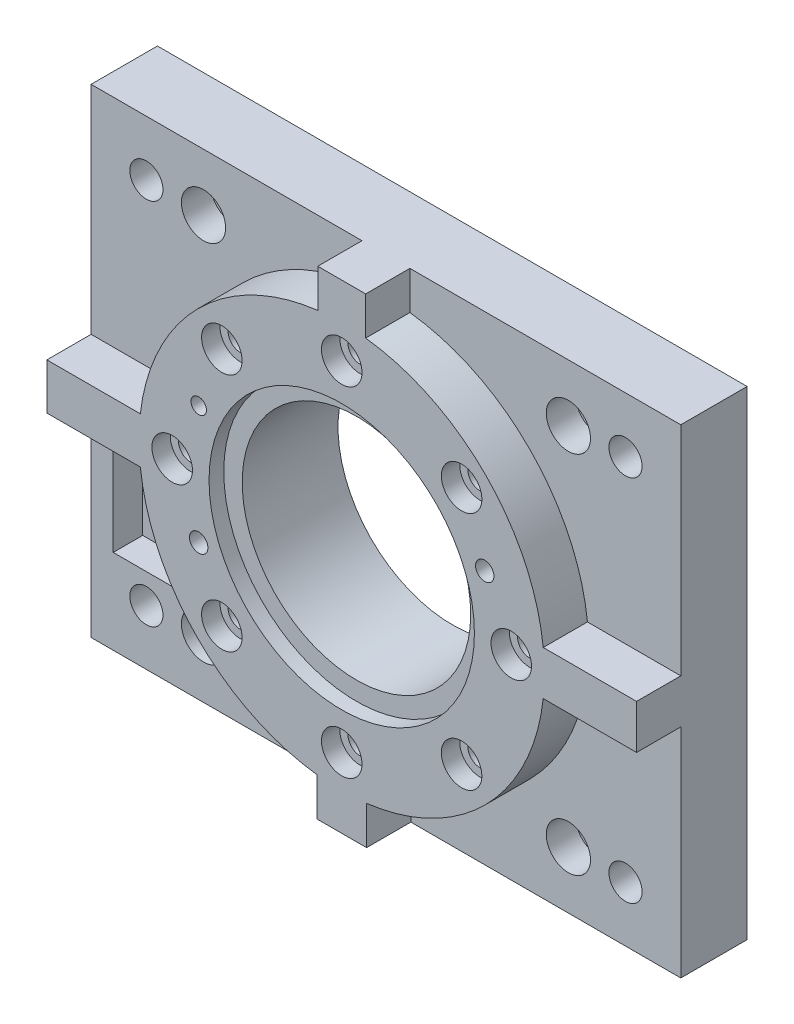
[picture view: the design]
ISO-10303-21;
HEADER;
FILE_DESCRIPTION(('STEP AP214'),'2;1');
FILE_NAME('part.step','',(''),(''),'','','');
FILE_SCHEMA(('AUTOMOTIVE_DESIGN { 1 0 10303 214 1 1 1 1 }'));
ENDSEC;
DATA;
#1=APPLICATION_CONTEXT('core data for automotive mechanical design processes');
#2=APPLICATION_PROTOCOL_DEFINITION('international standard','automotive_design',2000,#1);
#3=PRODUCT_CONTEXT('',#1,'mechanical');
#4=PRODUCT('Part','Part','',(#3));
#5=PRODUCT_RELATED_PRODUCT_CATEGORY('part','',(#4));
#6=PRODUCT_DEFINITION_FORMATION('','',#4);
#7=PRODUCT_DEFINITION_CONTEXT('part definition',#1,'design');
#8=PRODUCT_DEFINITION('design','',#6,#7);
#9=PRODUCT_DEFINITION_SHAPE('','',#8);
#10=(LENGTH_UNIT() NAMED_UNIT(*) SI_UNIT(.MILLI.,.METRE.));
#11=(NAMED_UNIT(*) PLANE_ANGLE_UNIT() SI_UNIT($,.RADIAN.));
#12=(NAMED_UNIT(*) SI_UNIT($,.STERADIAN.) SOLID_ANGLE_UNIT());
#13=UNCERTAINTY_MEASURE_WITH_UNIT(LENGTH_MEASURE(1.E-05),#10,'distance_accuracy_value','');
#14=(GEOMETRIC_REPRESENTATION_CONTEXT(3) GLOBAL_UNCERTAINTY_ASSIGNED_CONTEXT((#13)) GLOBAL_UNIT_ASSIGNED_CONTEXT((#10,
#11,#12)) REPRESENTATION_CONTEXT('',''));
#15=CARTESIAN_POINT('',(0.,0.,0.));
#16=DIRECTION('',(0.,0.,1.));
#17=DIRECTION('',(1.,0.,0.));
#18=AXIS2_PLACEMENT_3D('',#15,#16,#17);
#19=CARTESIAN_POINT('',(32.5269119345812,-32.5269119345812,0.));
#20=DIRECTION('',(0.,0.,1.));
#21=DIRECTION('',(1.,0.,0.));
#22=AXIS2_PLACEMENT_3D('',#19,#20,#21);
#23=CYLINDRICAL_SURFACE('',#22,3.3);
#24=CARTESIAN_POINT('',(32.5269119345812,-32.5269119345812,0.));
#25=DIRECTION('',(0.,0.,1.));
#26=DIRECTION('',(1.,0.,0.));
#27=AXIS2_PLACEMENT_3D('',#24,#25,#26);
#28=CIRCLE('',#27,3.3);
#29=CARTESIAN_POINT('',(35.8269119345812,-32.5269119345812,0.));
#30=VERTEX_POINT('',#29);
#31=EDGE_CURVE('E380',#30,#30,#28,.T.);
#32=ORIENTED_EDGE('',*,*,#31,.F.);
#33=EDGE_LOOP('',(#32));
#34=FACE_BOUND('',#33,.T.);
#35=CARTESIAN_POINT('',(32.5269119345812,-32.5269119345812,25.));
#36=DIRECTION('',(0.,0.,1.));
#37=DIRECTION('',(1.,0.,0.));
#38=AXIS2_PLACEMENT_3D('',#35,#36,#37);
#39=CIRCLE('',#38,3.3);
#40=CARTESIAN_POINT('',(35.8269119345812,-32.5269119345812,25.));
#41=VERTEX_POINT('',#40);
#42=EDGE_CURVE('E52',#41,#41,#39,.F.);
#43=ORIENTED_EDGE('',*,*,#42,.F.);
#44=EDGE_LOOP('',(#43));
#45=FACE_BOUND('',#44,.T.);
#46=ADVANCED_FACE('F47',(#34,#45),#23,.F.);
#47=CARTESIAN_POINT('',(0.,-46.,0.));
#48=DIRECTION('',(0.,0.,1.));
#49=DIRECTION('',(1.,0.,0.));
#50=AXIS2_PLACEMENT_3D('',#47,#48,#49);
#51=CYLINDRICAL_SURFACE('',#50,3.3);
#52=CARTESIAN_POINT('',(0.,-46.,0.));
#53=DIRECTION('',(0.,0.,1.));
#54=DIRECTION('',(1.,0.,0.));
#55=AXIS2_PLACEMENT_3D('',#52,#53,#54);
#56=CIRCLE('',#55,3.3);
#57=CARTESIAN_POINT('',(3.29999999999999,-46.,0.));
#58=VERTEX_POINT('',#57);
#59=EDGE_CURVE('E373',#58,#58,#56,.T.);
#60=ORIENTED_EDGE('',*,*,#59,.F.);
#61=EDGE_LOOP('',(#60));
#62=FACE_BOUND('',#61,.T.);
#63=CARTESIAN_POINT('',(0.,-46.,25.));
#64=DIRECTION('',(0.,0.,1.));
#65=DIRECTION('',(1.,0.,0.));
#66=AXIS2_PLACEMENT_3D('',#63,#64,#65);
#67=CIRCLE('',#66,3.3);
#68=CARTESIAN_POINT('',(3.29999999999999,-46.,25.));
#69=VERTEX_POINT('',#68);
#70=EDGE_CURVE('E577',#69,#69,#67,.F.);
#71=ORIENTED_EDGE('',*,*,#70,.F.);
#72=EDGE_LOOP('',(#71));
#73=FACE_BOUND('',#72,.T.);
#74=ADVANCED_FACE('F587',(#62,#73),#51,.F.);
#75=CARTESIAN_POINT('',(-32.5269119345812,-32.5269119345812,0.));
#76=DIRECTION('',(0.,0.,1.));
#77=DIRECTION('',(1.,0.,0.));
#78=AXIS2_PLACEMENT_3D('',#75,#76,#77);
#79=CYLINDRICAL_SURFACE('',#78,3.3);
#80=CARTESIAN_POINT('',(-32.5269119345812,-32.5269119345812,0.));
#81=DIRECTION('',(0.,0.,1.));
#82=DIRECTION('',(1.,0.,0.));
#83=AXIS2_PLACEMENT_3D('',#80,#81,#82);
#84=CIRCLE('',#83,3.3);
#85=CARTESIAN_POINT('',(-29.2269119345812,-32.5269119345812,0.));
#86=VERTEX_POINT('',#85);
#87=EDGE_CURVE('E367',#86,#86,#84,.T.);
#88=ORIENTED_EDGE('',*,*,#87,.F.);
#89=EDGE_LOOP('',(#88));
#90=FACE_BOUND('',#89,.T.);
#91=CARTESIAN_POINT('',(-32.5269119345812,-32.5269119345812,25.));
#92=DIRECTION('',(0.,0.,1.));
#93=DIRECTION('',(1.,0.,0.));
#94=AXIS2_PLACEMENT_3D('',#91,#92,#93);
#95=CIRCLE('',#94,3.3);
#96=CARTESIAN_POINT('',(-29.2269119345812,-32.5269119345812,25.));
#97=VERTEX_POINT('',#96);
#98=EDGE_CURVE('E573',#97,#97,#95,.F.);
#99=ORIENTED_EDGE('',*,*,#98,.F.);
#100=EDGE_LOOP('',(#99));
#101=FACE_BOUND('',#100,.T.);
#102=ADVANCED_FACE('F595',(#90,#101),#79,.F.);
#103=CARTESIAN_POINT('',(-46.,0.,0.));
#104=DIRECTION('',(0.,0.,1.));
#105=DIRECTION('',(1.,0.,0.));
#106=AXIS2_PLACEMENT_3D('',#103,#104,#105);
#107=CYLINDRICAL_SURFACE('',#106,3.3);
#108=CARTESIAN_POINT('',(-46.,0.,0.));
#109=DIRECTION('',(0.,0.,1.));
#110=DIRECTION('',(1.,0.,0.));
#111=AXIS2_PLACEMENT_3D('',#108,#109,#110);
#112=CIRCLE('',#111,3.3);
#113=CARTESIAN_POINT('',(-42.7,0.,0.));
#114=VERTEX_POINT('',#113);
#115=EDGE_CURVE('E362',#114,#114,#112,.T.);
#116=ORIENTED_EDGE('',*,*,#115,.F.);
#117=EDGE_LOOP('',(#116));
#118=FACE_BOUND('',#117,.T.);
#119=CARTESIAN_POINT('',(-46.,0.,25.));
#120=DIRECTION('',(0.,0.,1.));
#121=DIRECTION('',(1.,0.,0.));
#122=AXIS2_PLACEMENT_3D('',#119,#120,#121);
#123=CIRCLE('',#122,3.3);
#124=CARTESIAN_POINT('',(-42.7,0.,25.));
#125=VERTEX_POINT('',#124);
#126=EDGE_CURVE('E571',#125,#125,#123,.F.);
#127=ORIENTED_EDGE('',*,*,#126,.F.);
#128=EDGE_LOOP('',(#127));
#129=FACE_BOUND('',#128,.T.);
#130=ADVANCED_FACE('F799',(#118,#129),#107,.F.);
#131=CARTESIAN_POINT('',(-32.5269119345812,32.5269119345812,0.));
#132=DIRECTION('',(0.,0.,1.));
#133=DIRECTION('',(1.,0.,0.));
#134=AXIS2_PLACEMENT_3D('',#131,#132,#133);
#135=CYLINDRICAL_SURFACE('',#134,3.3);
#136=CARTESIAN_POINT('',(-32.5269119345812,32.5269119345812,0.));
#137=DIRECTION('',(0.,0.,1.));
#138=DIRECTION('',(1.,0.,0.));
#139=AXIS2_PLACEMENT_3D('',#136,#137,#138);
#140=CIRCLE('',#139,3.3);
#141=CARTESIAN_POINT('',(-29.2269119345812,32.5269119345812,0.));
#142=VERTEX_POINT('',#141);
#143=EDGE_CURVE('E363',#142,#142,#140,.T.);
#144=ORIENTED_EDGE('',*,*,#143,.F.);
#145=EDGE_LOOP('',(#144));
#146=FACE_BOUND('',#145,.T.);
#147=CARTESIAN_POINT('',(-32.5269119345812,32.5269119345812,25.));
#148=DIRECTION('',(0.,0.,1.));
#149=DIRECTION('',(1.,0.,0.));
#150=AXIS2_PLACEMENT_3D('',#147,#148,#149);
#151=CIRCLE('',#150,3.3);
#152=CARTESIAN_POINT('',(-29.2269119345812,32.5269119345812,25.));
#153=VERTEX_POINT('',#152);
#154=EDGE_CURVE('E568',#153,#153,#151,.F.);
#155=ORIENTED_EDGE('',*,*,#154,.F.);
#156=EDGE_LOOP('',(#155));
#157=FACE_BOUND('',#156,.T.);
#158=ADVANCED_FACE('F807',(#146,#157),#135,.F.);
#159=CARTESIAN_POINT('',(0.,46.,0.));
#160=DIRECTION('',(0.,0.,1.));
#161=DIRECTION('',(1.,0.,0.));
#162=AXIS2_PLACEMENT_3D('',#159,#160,#161);
#163=CYLINDRICAL_SURFACE('',#162,3.3);
#164=CARTESIAN_POINT('',(0.,46.,0.));
#165=DIRECTION('',(0.,0.,1.));
#166=DIRECTION('',(1.,0.,0.));
#167=AXIS2_PLACEMENT_3D('',#164,#165,#166);
#168=CIRCLE('',#167,3.3);
#169=CARTESIAN_POINT('',(3.3,46.,0.));
#170=VERTEX_POINT('',#169);
#171=EDGE_CURVE('E357',#170,#170,#168,.T.);
#172=ORIENTED_EDGE('',*,*,#171,.F.);
#173=EDGE_LOOP('',(#172));
#174=FACE_BOUND('',#173,.T.);
#175=CARTESIAN_POINT('',(0.,46.,25.));
#176=DIRECTION('',(0.,0.,1.));
#177=DIRECTION('',(1.,0.,0.));
#178=AXIS2_PLACEMENT_3D('',#175,#176,#177);
#179=CIRCLE('',#178,3.3);
#180=CARTESIAN_POINT('',(3.3,46.,25.));
#181=VERTEX_POINT('',#180);
#182=EDGE_CURVE('E564',#181,#181,#179,.F.);
#183=ORIENTED_EDGE('',*,*,#182,.F.);
#184=EDGE_LOOP('',(#183));
#185=FACE_BOUND('',#184,.T.);
#186=ADVANCED_FACE('F814',(#174,#185),#163,.F.);
#187=CARTESIAN_POINT('',(32.5269119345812,32.5269119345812,0.));
#188=DIRECTION('',(0.,0.,1.));
#189=DIRECTION('',(1.,0.,0.));
#190=AXIS2_PLACEMENT_3D('',#187,#188,#189);
#191=CYLINDRICAL_SURFACE('',#190,3.3);
#192=CARTESIAN_POINT('',(32.5269119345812,32.5269119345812,0.));
#193=DIRECTION('',(0.,0.,1.));
#194=DIRECTION('',(1.,0.,0.));
#195=AXIS2_PLACEMENT_3D('',#192,#193,#194);
#196=CIRCLE('',#195,3.3);
#197=CARTESIAN_POINT('',(35.8269119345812,32.5269119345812,0.));
#198=VERTEX_POINT('',#197);
#199=EDGE_CURVE('E354',#198,#198,#196,.T.);
#200=ORIENTED_EDGE('',*,*,#199,.F.);
#201=EDGE_LOOP('',(#200));
#202=FACE_BOUND('',#201,.T.);
#203=CARTESIAN_POINT('',(32.5269119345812,32.5269119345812,25.));
#204=DIRECTION('',(0.,0.,1.));
#205=DIRECTION('',(1.,0.,0.));
#206=AXIS2_PLACEMENT_3D('',#203,#204,#205);
#207=CIRCLE('',#206,3.3);
#208=CARTESIAN_POINT('',(35.8269119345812,32.5269119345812,25.));
#209=VERTEX_POINT('',#208);
#210=EDGE_CURVE('E565',#209,#209,#207,.F.);
#211=ORIENTED_EDGE('',*,*,#210,.F.);
#212=EDGE_LOOP('',(#211));
#213=FACE_BOUND('',#212,.T.);
#214=ADVANCED_FACE('F822',(#202,#213),#191,.F.);
#215=CARTESIAN_POINT('',(46.,0.,0.));
#216=DIRECTION('',(0.,0.,1.));
#217=DIRECTION('',(1.,0.,0.));
#218=AXIS2_PLACEMENT_3D('',#215,#216,#217);
#219=CYLINDRICAL_SURFACE('',#218,3.3);
#220=CARTESIAN_POINT('',(46.,0.,0.));
#221=DIRECTION('',(0.,0.,1.));
#222=DIRECTION('',(1.,0.,0.));
#223=AXIS2_PLACEMENT_3D('',#220,#221,#222);
#224=CIRCLE('',#223,3.3);
#225=CARTESIAN_POINT('',(49.3,0.,0.));
#226=VERTEX_POINT('',#225);
#227=EDGE_CURVE('E349',#226,#226,#224,.T.);
#228=ORIENTED_EDGE('',*,*,#227,.F.);
#229=EDGE_LOOP('',(#228));
#230=FACE_BOUND('',#229,.T.);
#231=CARTESIAN_POINT('',(46.,0.,25.));
#232=DIRECTION('',(0.,0.,1.));
#233=DIRECTION('',(1.,0.,0.));
#234=AXIS2_PLACEMENT_3D('',#231,#232,#233);
#235=CIRCLE('',#234,3.3);
#236=CARTESIAN_POINT('',(49.3,0.,25.));
#237=VERTEX_POINT('',#236);
#238=EDGE_CURVE('E298',#237,#237,#235,.F.);
#239=ORIENTED_EDGE('',*,*,#238,.F.);
#240=EDGE_LOOP('',(#239));
#241=FACE_BOUND('',#240,.T.);
#242=ADVANCED_FACE('F615',(#230,#241),#219,.F.);
#243=CARTESIAN_POINT('',(0.,0.,0.));
#244=DIRECTION('',(0.,0.,1.));
#245=DIRECTION('',(1.,0.,0.));
#246=AXIS2_PLACEMENT_3D('',#243,#244,#245);
#247=CYLINDRICAL_SURFACE('',#246,31.);
#248=CARTESIAN_POINT('',(0.,0.,0.));
#249=DIRECTION('',(0.,0.,1.));
#250=DIRECTION('',(1.,0.,0.));
#251=AXIS2_PLACEMENT_3D('',#248,#249,#250);
#252=CIRCLE('',#251,31.);
#253=CARTESIAN_POINT('',(31.,0.,0.));
#254=VERTEX_POINT('',#253);
#255=EDGE_CURVE('E389',#254,#254,#252,.T.);
#256=ORIENTED_EDGE('',*,*,#255,.F.);
#257=EDGE_LOOP('',(#256));
#258=FACE_BOUND('',#257,.T.);
#259=CARTESIAN_POINT('',(0.,0.,26.));
#260=DIRECTION('',(0.,0.,1.));
#261=DIRECTION('',(1.,0.,0.));
#262=AXIS2_PLACEMENT_3D('',#259,#260,#261);
#263=CIRCLE('',#262,31.);
#264=CARTESIAN_POINT('',(31.,0.,26.));
#265=VERTEX_POINT('',#264);
#266=EDGE_CURVE('E383',#265,#265,#263,.F.);
#267=ORIENTED_EDGE('',*,*,#266,.F.);
#268=EDGE_LOOP('',(#267));
#269=FACE_BOUND('',#268,.T.);
#270=ADVANCED_FACE('F609',(#258,#269),#247,.F.);
#271=CARTESIAN_POINT('',(0.,0.,30.));
#272=DIRECTION('',(0.,0.,-1.));
#273=DIRECTION('',(-1.,0.,0.));
#274=AXIS2_PLACEMENT_3D('',#271,#272,#273);
#275=CYLINDRICAL_SURFACE('',#274,55.);
#276=DIRECTION('',(0.,0.,-1.));
#277=VECTOR('',#276,1.);
#278=CARTESIAN_POINT('',(-6.75,-54.5842239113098,30.));
#279=LINE('',#278,#277);
#280=CARTESIAN_POINT('',(-6.75,-54.5842239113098,30.));
#281=VERTEX_POINT('',#280);
#282=CARTESIAN_POINT('',(-6.75,-54.5842239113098,18.));
#283=VERTEX_POINT('',#282);
#284=EDGE_CURVE('E420',#281,#283,#279,.T.);
#285=ORIENTED_EDGE('',*,*,#284,.F.);
#286=CARTESIAN_POINT('',(0.,0.,30.));
#287=DIRECTION('',(0.,0.,1.));
#288=DIRECTION('',(1.,0.,0.));
#289=AXIS2_PLACEMENT_3D('',#286,#287,#288);
#290=CIRCLE('',#289,55.);
#291=CARTESIAN_POINT('',(-54.643732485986,-6.25,30.));
#292=VERTEX_POINT('',#291);
#293=EDGE_CURVE('E516',#292,#281,#290,.T.);
#294=ORIENTED_EDGE('',*,*,#293,.F.);
#295=DIRECTION('',(0.,0.,-1.));
#296=VECTOR('',#295,1.);
#297=CARTESIAN_POINT('',(-54.643732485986,-6.25,30.));
#298=LINE('',#297,#296);
#299=CARTESIAN_POINT('',(-54.643732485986,-6.25,18.));
#300=VERTEX_POINT('',#299);
#301=EDGE_CURVE('E479',#300,#292,#298,.F.);
#302=ORIENTED_EDGE('',*,*,#301,.F.);
#303=CARTESIAN_POINT('',(0.,0.,18.));
#304=DIRECTION('',(0.,0.,1.));
#305=DIRECTION('',(1.,0.,0.));
#306=AXIS2_PLACEMENT_3D('',#303,#304,#305);
#307=CIRCLE('',#306,55.);
#308=EDGE_CURVE('E61',#300,#283,#307,.T.);
#309=ORIENTED_EDGE('',*,*,#308,.T.);
#310=EDGE_LOOP('',(#285,#294,#302,#309));
#311=FACE_BOUND('',#310,.T.);
#312=ADVANCED_FACE('F612',(#311),#275,.T.);
#313=DIRECTION('',(0.,0.,-1.));
#314=VECTOR('',#313,1.);
#315=CARTESIAN_POINT('',(6.75,-54.5842239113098,30.));
#316=LINE('',#315,#314);
#317=CARTESIAN_POINT('',(6.75,-54.5842239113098,18.));
#318=VERTEX_POINT('',#317);
#319=CARTESIAN_POINT('',(6.75,-54.5842239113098,30.));
#320=VERTEX_POINT('',#319);
#321=EDGE_CURVE('E77',#318,#320,#316,.F.);
#322=ORIENTED_EDGE('',*,*,#321,.F.);
#323=CARTESIAN_POINT('',(54.6717477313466,-6.,18.));
#324=VERTEX_POINT('',#323);
#325=EDGE_CURVE('E58',#318,#324,#307,.T.);
#326=ORIENTED_EDGE('',*,*,#325,.T.);
#327=DIRECTION('',(0.,0.,-1.));
#328=VECTOR('',#327,1.);
#329=CARTESIAN_POINT('',(54.6717477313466,-6.,30.));
#330=LINE('',#329,#328);
#331=CARTESIAN_POINT('',(54.6717477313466,-6.,30.));
#332=VERTEX_POINT('',#331);
#333=EDGE_CURVE('E507',#332,#324,#330,.T.);
#334=ORIENTED_EDGE('',*,*,#333,.F.);
#335=EDGE_CURVE('E512',#320,#332,#290,.T.);
#336=ORIENTED_EDGE('',*,*,#335,.F.);
#337=EDGE_LOOP('',(#322,#326,#334,#336));
#338=FACE_BOUND('',#337,.T.);
#339=ADVANCED_FACE('F655',(#338),#275,.T.);
#340=CARTESIAN_POINT('',(0.,0.,18.));
#341=DIRECTION('',(0.,0.,1.));
#342=DIRECTION('',(1.,0.,0.));
#343=AXIS2_PLACEMENT_3D('',#340,#341,#342);
#344=PLANE('',#343);
#345=CARTESIAN_POINT('',(-49.4974746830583,-49.4974746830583,18.));
#346=DIRECTION('',(0.,0.,1.));
#347=DIRECTION('',(1.,0.,0.));
#348=AXIS2_PLACEMENT_3D('',#345,#346,#347);
#349=CIRCLE('',#348,6.);
#350=CARTESIAN_POINT('',(-43.4974746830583,-49.4974746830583,18.));
#351=VERTEX_POINT('',#350);
#352=EDGE_CURVE('E1309',#351,#351,#349,.T.);
#353=ORIENTED_EDGE('',*,*,#352,.F.);
#354=EDGE_LOOP('',(#353));
#355=FACE_BOUND('',#354,.T.);
#356=DIRECTION('',(0.,-1.,0.));
#357=VECTOR('',#356,1.);
#358=CARTESIAN_POINT('',(-74.,-14.,18.));
#359=LINE('',#358,#357);
#360=CARTESIAN_POINT('',(-74.,-14.,18.));
#361=VERTEX_POINT('',#360);
#362=CARTESIAN_POINT('',(-74.,-42.,18.));
#363=VERTEX_POINT('',#362);
#364=EDGE_CURVE('E69',#361,#363,#359,.T.);
#365=ORIENTED_EDGE('',*,*,#364,.F.);
#366=DIRECTION('',(-1.,0.,0.));
#367=VECTOR('',#366,1.);
#368=CARTESIAN_POINT('',(-58.,-14.,18.));
#369=LINE('',#368,#367);
#370=CARTESIAN_POINT('',(-58.,-14.,18.));
#371=VERTEX_POINT('',#370);
#372=EDGE_CURVE('E236',#371,#361,#369,.T.);
#373=ORIENTED_EDGE('',*,*,#372,.F.);
#374=DIRECTION('',(0.,1.,0.));
#375=VECTOR('',#374,1.);
#376=CARTESIAN_POINT('',(-58.,-42.,18.));
#377=LINE('',#376,#375);
#378=CARTESIAN_POINT('',(-58.,-42.,18.));
#379=VERTEX_POINT('',#378);
#380=EDGE_CURVE('E239',#379,#371,#377,.T.);
#381=ORIENTED_EDGE('',*,*,#380,.F.);
#382=DIRECTION('',(1.,0.,0.));
#383=VECTOR('',#382,1.);
#384=CARTESIAN_POINT('',(-74.,-42.,18.));
#385=LINE('',#384,#383);
#386=EDGE_CURVE('E252',#363,#379,#385,.T.);
#387=ORIENTED_EDGE('',*,*,#386,.F.);
#388=EDGE_LOOP('',(#365,#373,#381,#387));
#389=FACE_BOUND('',#388,.T.);
#390=CARTESIAN_POINT('',(-65.,-50.,18.));
#391=DIRECTION('',(0.,0.,1.));
#392=DIRECTION('',(1.,0.,0.));
#393=AXIS2_PLACEMENT_3D('',#390,#391,#392);
#394=CIRCLE('',#393,4.5);
#395=CARTESIAN_POINT('',(-60.5,-50.,18.));
#396=VERTEX_POINT('',#395);
#397=EDGE_CURVE('E271',#396,#396,#394,.T.);
#398=ORIENTED_EDGE('',*,*,#397,.F.);
#399=EDGE_LOOP('',(#398));
#400=FACE_BOUND('',#399,.T.);
#401=DIRECTION('',(0.,-1.,0.));
#402=VECTOR('',#401,1.);
#403=CARTESIAN_POINT('',(-6.75,-50.,18.));
#404=LINE('',#403,#402);
#405=CARTESIAN_POINT('',(-6.75000000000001,-65.,18.));
#406=VERTEX_POINT('',#405);
#407=EDGE_CURVE('E395',#283,#406,#404,.T.);
#408=ORIENTED_EDGE('',*,*,#407,.F.);
#409=ORIENTED_EDGE('',*,*,#308,.F.);
#410=DIRECTION('',(1.,0.,0.));
#411=VECTOR('',#410,1.);
#412=CARTESIAN_POINT('',(-80.,-6.25,18.));
#413=LINE('',#412,#411);
#414=CARTESIAN_POINT('',(-80.,-6.25000000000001,18.));
#415=VERTEX_POINT('',#414);
#416=EDGE_CURVE('E448',#415,#300,#413,.T.);
#417=ORIENTED_EDGE('',*,*,#416,.F.);
#418=DIRECTION('',(0.,-1.,0.));
#419=VECTOR('',#418,1.);
#420=CARTESIAN_POINT('',(-80.,65.,18.));
#421=LINE('',#420,#419);
#422=CARTESIAN_POINT('',(-80.,-65.,18.));
#423=VERTEX_POINT('',#422);
#424=EDGE_CURVE('E525',#415,#423,#421,.T.);
#425=ORIENTED_EDGE('',*,*,#424,.T.);
#426=DIRECTION('',(1.,0.,0.));
#427=VECTOR('',#426,1.);
#428=CARTESIAN_POINT('',(-80.,-65.,18.));
#429=LINE('',#428,#427);
#430=EDGE_CURVE('E524',#423,#406,#429,.T.);
#431=ORIENTED_EDGE('',*,*,#430,.T.);
#432=EDGE_LOOP('',(#408,#409,#417,#425,#431));
#433=FACE_BOUND('',#432,.T.);
#434=ADVANCED_FACE('F658',(#355,#389,#400,#433),#344,.T.);
#435=DIRECTION('',(0.,0.,-1.));
#436=VECTOR('',#435,1.);
#437=CARTESIAN_POINT('',(-6.5,54.6145584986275,30.));
#438=LINE('',#437,#436);
#439=CARTESIAN_POINT('',(-6.5,54.6145584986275,18.));
#440=VERTEX_POINT('',#439);
#441=CARTESIAN_POINT('',(-6.5,54.6145584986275,30.));
#442=VERTEX_POINT('',#441);
#443=EDGE_CURVE('E450',#440,#442,#438,.F.);
#444=ORIENTED_EDGE('',*,*,#443,.F.);
#445=CARTESIAN_POINT('',(-54.643732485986,6.25,18.));
#446=VERTEX_POINT('',#445);
#447=EDGE_CURVE('E59',#440,#446,#307,.T.);
#448=ORIENTED_EDGE('',*,*,#447,.T.);
#449=DIRECTION('',(0.,0.,-1.));
#450=VECTOR('',#449,1.);
#451=CARTESIAN_POINT('',(-54.643732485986,6.25,30.));
#452=LINE('',#451,#450);
#453=CARTESIAN_POINT('',(-54.643732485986,6.25,30.));
#454=VERTEX_POINT('',#453);
#455=EDGE_CURVE('E475',#454,#446,#452,.T.);
#456=ORIENTED_EDGE('',*,*,#455,.F.);
#457=EDGE_CURVE('E513',#442,#454,#290,.T.);
#458=ORIENTED_EDGE('',*,*,#457,.F.);
#459=EDGE_LOOP('',(#444,#448,#456,#458));
#460=FACE_BOUND('',#459,.T.);
#461=ADVANCED_FACE('F699',(#460),#275,.T.);
#462=DIRECTION('',(0.,0.,-1.));
#463=VECTOR('',#462,1.);
#464=CARTESIAN_POINT('',(6.5,54.6145584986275,30.));
#465=LINE('',#464,#463);
#466=CARTESIAN_POINT('',(6.5,54.6145584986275,30.));
#467=VERTEX_POINT('',#466);
#468=CARTESIAN_POINT('',(6.5,54.6145584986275,18.));
#469=VERTEX_POINT('',#468);
#470=EDGE_CURVE('E443',#467,#469,#465,.T.);
#471=ORIENTED_EDGE('',*,*,#470,.F.);
#472=CARTESIAN_POINT('',(54.6717477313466,6.,30.));
#473=VERTEX_POINT('',#472);
#474=EDGE_CURVE('E515',#473,#467,#290,.T.);
#475=ORIENTED_EDGE('',*,*,#474,.F.);
#476=DIRECTION('',(0.,0.,-1.));
#477=VECTOR('',#476,1.);
#478=CARTESIAN_POINT('',(54.6717477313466,6.,30.));
#479=LINE('',#478,#477);
#480=CARTESIAN_POINT('',(54.6717477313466,6.,18.));
#481=VERTEX_POINT('',#480);
#482=EDGE_CURVE('E504',#481,#473,#479,.F.);
#483=ORIENTED_EDGE('',*,*,#482,.F.);
#484=EDGE_CURVE('E12',#481,#469,#307,.T.);
#485=ORIENTED_EDGE('',*,*,#484,.T.);
#486=EDGE_LOOP('',(#471,#475,#483,#485));
#487=FACE_BOUND('',#486,.T.);
#488=ADVANCED_FACE('F651',(#487),#275,.T.);
#489=CARTESIAN_POINT('',(-49.4974746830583,49.4974746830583,18.));
#490=DIRECTION('',(0.,0.,1.));
#491=DIRECTION('',(1.,0.,0.));
#492=AXIS2_PLACEMENT_3D('',#489,#490,#491);
#493=CIRCLE('',#492,6.);
#494=CARTESIAN_POINT('',(-43.4974746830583,49.4974746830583,18.));
#495=VERTEX_POINT('',#494);
#496=EDGE_CURVE('E1302',#495,#495,#493,.T.);
#497=ORIENTED_EDGE('',*,*,#496,.F.);
#498=EDGE_LOOP('',(#497));
#499=FACE_BOUND('',#498,.T.);
#500=CARTESIAN_POINT('',(-65.,50.,18.));
#501=DIRECTION('',(0.,0.,1.));
#502=DIRECTION('',(1.,0.,0.));
#503=AXIS2_PLACEMENT_3D('',#500,#501,#502);
#504=CIRCLE('',#503,4.5);
#505=CARTESIAN_POINT('',(-60.5,50.,18.));
#506=VERTEX_POINT('',#505);
#507=EDGE_CURVE('E287',#506,#506,#504,.T.);
#508=ORIENTED_EDGE('',*,*,#507,.F.);
#509=EDGE_LOOP('',(#508));
#510=FACE_BOUND('',#509,.T.);
#511=DIRECTION('',(0.,-1.,0.));
#512=VECTOR('',#511,1.);
#513=CARTESIAN_POINT('',(-6.5,65.,18.));
#514=LINE('',#513,#512);
#515=CARTESIAN_POINT('',(-6.50000000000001,65.,18.));
#516=VERTEX_POINT('',#515);
#517=EDGE_CURVE('E418',#516,#440,#514,.T.);
#518=ORIENTED_EDGE('',*,*,#517,.F.);
#519=DIRECTION('',(-1.,0.,0.));
#520=VECTOR('',#519,1.);
#521=CARTESIAN_POINT('',(80.,65.,18.));
#522=LINE('',#521,#520);
#523=CARTESIAN_POINT('',(-80.,65.,18.));
#524=VERTEX_POINT('',#523);
#525=EDGE_CURVE('E528',#516,#524,#522,.T.);
#526=ORIENTED_EDGE('',*,*,#525,.T.);
#527=CARTESIAN_POINT('',(-80.,6.25,18.));
#528=VERTEX_POINT('',#527);
#529=EDGE_CURVE('E519',#524,#528,#421,.T.);
#530=ORIENTED_EDGE('',*,*,#529,.T.);
#531=DIRECTION('',(-1.,0.,0.));
#532=VECTOR('',#531,1.);
#533=CARTESIAN_POINT('',(-50.,6.25,18.));
#534=LINE('',#533,#532);
#535=EDGE_CURVE('E457',#446,#528,#534,.T.);
#536=ORIENTED_EDGE('',*,*,#535,.F.);
#537=ORIENTED_EDGE('',*,*,#447,.F.);
#538=EDGE_LOOP('',(#518,#526,#530,#536,#537));
#539=FACE_BOUND('',#538,.T.);
#540=ADVANCED_FACE('F694',(#499,#510,#539),#344,.T.);
#541=CARTESIAN_POINT('',(49.4974746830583,49.4974746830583,18.));
#542=DIRECTION('',(0.,0.,1.));
#543=DIRECTION('',(1.,0.,0.));
#544=AXIS2_PLACEMENT_3D('',#541,#542,#543);
#545=CIRCLE('',#544,6.);
#546=CARTESIAN_POINT('',(55.4974746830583,49.4974746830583,18.));
#547=VERTEX_POINT('',#546);
#548=EDGE_CURVE('E243',#547,#547,#545,.T.);
#549=ORIENTED_EDGE('',*,*,#548,.F.);
#550=EDGE_LOOP('',(#549));
#551=FACE_BOUND('',#550,.T.);
#552=CARTESIAN_POINT('',(65.,50.,18.));
#553=DIRECTION('',(0.,0.,1.));
#554=DIRECTION('',(1.,0.,0.));
#555=AXIS2_PLACEMENT_3D('',#552,#553,#554);
#556=CIRCLE('',#555,4.5);
#557=CARTESIAN_POINT('',(69.5,50.,18.));
#558=VERTEX_POINT('',#557);
#559=EDGE_CURVE('E284',#558,#558,#556,.T.);
#560=ORIENTED_EDGE('',*,*,#559,.F.);
#561=EDGE_LOOP('',(#560));
#562=FACE_BOUND('',#561,.T.);
#563=DIRECTION('',(0.,1.,0.));
#564=VECTOR('',#563,1.);
#565=CARTESIAN_POINT('',(6.5,50.,18.));
#566=LINE('',#565,#564);
#567=CARTESIAN_POINT('',(6.50000000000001,65.,18.));
#568=VERTEX_POINT('',#567);
#569=EDGE_CURVE('E428',#469,#568,#566,.T.);
#570=ORIENTED_EDGE('',*,*,#569,.F.);
#571=ORIENTED_EDGE('',*,*,#484,.F.);
#572=DIRECTION('',(-1.,0.,0.));
#573=VECTOR('',#572,1.);
#574=CARTESIAN_POINT('',(80.,6.,18.));
#575=LINE('',#574,#573);
#576=CARTESIAN_POINT('',(80.,6.00000000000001,18.));
#577=VERTEX_POINT('',#576);
#578=EDGE_CURVE('E488',#577,#481,#575,.T.);
#579=ORIENTED_EDGE('',*,*,#578,.F.);
#580=DIRECTION('',(0.,1.,0.));
#581=VECTOR('',#580,1.);
#582=CARTESIAN_POINT('',(80.,-65.,18.));
#583=LINE('',#582,#581);
#584=CARTESIAN_POINT('',(80.,65.,18.));
#585=VERTEX_POINT('',#584);
#586=EDGE_CURVE('E527',#577,#585,#583,.T.);
#587=ORIENTED_EDGE('',*,*,#586,.T.);
#588=EDGE_CURVE('E532',#585,#568,#522,.T.);
#589=ORIENTED_EDGE('',*,*,#588,.T.);
#590=EDGE_LOOP('',(#570,#571,#579,#587,#589));
#591=FACE_BOUND('',#590,.T.);
#592=ADVANCED_FACE('F662',(#551,#562,#591),#344,.T.);
#593=CARTESIAN_POINT('',(-80.,65.,18.));
#594=DIRECTION('',(1.,0.,0.));
#595=DIRECTION('',(0.,0.,-1.));
#596=AXIS2_PLACEMENT_3D('',#593,#594,#595);
#597=PLANE('',#596);
#598=DIRECTION('',(0.,-1.,0.));
#599=VECTOR('',#598,1.);
#600=CARTESIAN_POINT('',(-80.,65.,0.));
#601=LINE('',#600,#599);
#602=CARTESIAN_POINT('',(-80.,65.,0.));
#603=VERTEX_POINT('',#602);
#604=CARTESIAN_POINT('',(-80.,-65.,0.));
#605=VERTEX_POINT('',#604);
#606=EDGE_CURVE('E511',#603,#605,#601,.T.);
#607=ORIENTED_EDGE('',*,*,#606,.T.);
#608=DIRECTION('',(0.,0.,-1.));
#609=VECTOR('',#608,1.);
#610=CARTESIAN_POINT('',(-80.,-65.,18.));
#611=LINE('',#610,#609);
#612=EDGE_CURVE('E555',#423,#605,#611,.T.);
#613=ORIENTED_EDGE('',*,*,#612,.F.);
#614=ORIENTED_EDGE('',*,*,#424,.F.);
#615=DIRECTION('',(0.,0.,-1.));
#616=VECTOR('',#615,1.);
#617=CARTESIAN_POINT('',(-80.,-6.25,30.));
#618=LINE('',#617,#616);
#619=CARTESIAN_POINT('',(-80.,-6.25,30.));
#620=VERTEX_POINT('',#619);
#621=EDGE_CURVE('E471',#620,#415,#618,.T.);
#622=ORIENTED_EDGE('',*,*,#621,.F.);
#623=DIRECTION('',(0.,-1.,0.));
#624=VECTOR('',#623,1.);
#625=CARTESIAN_POINT('',(-80.,6.25,30.));
#626=LINE('',#625,#624);
#627=CARTESIAN_POINT('',(-80.,6.25,30.));
#628=VERTEX_POINT('',#627);
#629=EDGE_CURVE('E451',#628,#620,#626,.T.);
#630=ORIENTED_EDGE('',*,*,#629,.F.);
#631=DIRECTION('',(0.,0.,-1.));
#632=VECTOR('',#631,1.);
#633=CARTESIAN_POINT('',(-80.,6.25,30.));
#634=LINE('',#633,#632);
#635=EDGE_CURVE('E464',#628,#528,#634,.T.);
#636=ORIENTED_EDGE('',*,*,#635,.T.);
#637=ORIENTED_EDGE('',*,*,#529,.F.);
#638=DIRECTION('',(0.,0.,-1.));
#639=VECTOR('',#638,1.);
#640=CARTESIAN_POINT('',(-80.,65.,18.));
#641=LINE('',#640,#639);
#642=EDGE_CURVE('E534',#524,#603,#641,.T.);
#643=ORIENTED_EDGE('',*,*,#642,.T.);
#644=EDGE_LOOP('',(#607,#613,#614,#622,#630,#636,#637,#643));
#645=FACE_BOUND('',#644,.T.);
#646=ADVANCED_FACE('F51',(#645),#597,.F.);
#647=CARTESIAN_POINT('',(-80.,-65.,18.));
#648=DIRECTION('',(0.,1.,0.));
#649=DIRECTION('',(0.,0.,1.));
#650=AXIS2_PLACEMENT_3D('',#647,#648,#649);
#651=PLANE('',#650);
#652=DIRECTION('',(1.,0.,0.));
#653=VECTOR('',#652,1.);
#654=CARTESIAN_POINT('',(-80.,-65.,0.));
#655=LINE('',#654,#653);
#656=CARTESIAN_POINT('',(80.,-65.,0.));
#657=VERTEX_POINT('',#656);
#658=EDGE_CURVE('E537',#605,#657,#655,.T.);
#659=ORIENTED_EDGE('',*,*,#658,.T.);
#660=DIRECTION('',(0.,0.,-1.));
#661=VECTOR('',#660,1.);
#662=CARTESIAN_POINT('',(80.,-65.,18.));
#663=LINE('',#662,#661);
#664=CARTESIAN_POINT('',(80.,-65.,18.));
#665=VERTEX_POINT('',#664);
#666=EDGE_CURVE('E548',#665,#657,#663,.T.);
#667=ORIENTED_EDGE('',*,*,#666,.F.);
#668=CARTESIAN_POINT('',(6.75000000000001,-65.,18.));
#669=VERTEX_POINT('',#668);
#670=EDGE_CURVE('E522',#669,#665,#429,.T.);
#671=ORIENTED_EDGE('',*,*,#670,.F.);
#672=DIRECTION('',(0.,0.,-1.));
#673=VECTOR('',#672,1.);
#674=CARTESIAN_POINT('',(6.75,-65.,30.));
#675=LINE('',#674,#673);
#676=CARTESIAN_POINT('',(6.75,-65.,30.));
#677=VERTEX_POINT('',#676);
#678=EDGE_CURVE('E404',#677,#669,#675,.T.);
#679=ORIENTED_EDGE('',*,*,#678,.F.);
#680=DIRECTION('',(1.,0.,0.));
#681=VECTOR('',#680,1.);
#682=CARTESIAN_POINT('',(-6.75,-65.,30.));
#683=LINE('',#682,#681);
#684=CARTESIAN_POINT('',(-6.75,-65.,30.));
#685=VERTEX_POINT('',#684);
#686=EDGE_CURVE('E397',#685,#677,#683,.T.);
#687=ORIENTED_EDGE('',*,*,#686,.F.);
#688=DIRECTION('',(0.,0.,-1.));
#689=VECTOR('',#688,1.);
#690=CARTESIAN_POINT('',(-6.75,-65.,30.));
#691=LINE('',#690,#689);
#692=EDGE_CURVE('E415',#685,#406,#691,.T.);
#693=ORIENTED_EDGE('',*,*,#692,.T.);
#694=ORIENTED_EDGE('',*,*,#430,.F.);
#695=ORIENTED_EDGE('',*,*,#612,.T.);
#696=EDGE_LOOP('',(#659,#667,#671,#679,#687,#693,#694,#695));
#697=FACE_BOUND('',#696,.T.);
#698=ADVANCED_FACE('F670',(#697),#651,.F.);
#699=CARTESIAN_POINT('',(80.,-65.,18.));
#700=DIRECTION('',(-1.,0.,0.));
#701=DIRECTION('',(0.,0.,1.));
#702=AXIS2_PLACEMENT_3D('',#699,#700,#701);
#703=PLANE('',#702);
#704=DIRECTION('',(0.,1.,0.));
#705=VECTOR('',#704,1.);
#706=CARTESIAN_POINT('',(80.,-65.,0.));
#707=LINE('',#706,#705);
#708=CARTESIAN_POINT('',(80.,65.,0.));
#709=VERTEX_POINT('',#708);
#710=EDGE_CURVE('E538',#657,#709,#707,.T.);
#711=ORIENTED_EDGE('',*,*,#710,.T.);
#712=DIRECTION('',(0.,0.,-1.));
#713=VECTOR('',#712,1.);
#714=CARTESIAN_POINT('',(80.,65.,18.));
#715=LINE('',#714,#713);
#716=EDGE_CURVE('E547',#585,#709,#715,.T.);
#717=ORIENTED_EDGE('',*,*,#716,.F.);
#718=ORIENTED_EDGE('',*,*,#586,.F.);
#719=DIRECTION('',(0.,0.,-1.));
#720=VECTOR('',#719,1.);
#721=CARTESIAN_POINT('',(80.,6.,30.));
#722=LINE('',#721,#720);
#723=CARTESIAN_POINT('',(80.,6.,30.));
#724=VERTEX_POINT('',#723);
#725=EDGE_CURVE('E491',#724,#577,#722,.T.);
#726=ORIENTED_EDGE('',*,*,#725,.F.);
#727=DIRECTION('',(0.,1.,0.));
#728=VECTOR('',#727,1.);
#729=CARTESIAN_POINT('',(80.,-6.,30.));
#730=LINE('',#729,#728);
#731=CARTESIAN_POINT('',(80.,-6.,30.));
#732=VERTEX_POINT('',#731);
#733=EDGE_CURVE('E483',#732,#724,#730,.T.);
#734=ORIENTED_EDGE('',*,*,#733,.F.);
#735=DIRECTION('',(0.,0.,-1.));
#736=VECTOR('',#735,1.);
#737=CARTESIAN_POINT('',(80.,-6.,30.));
#738=LINE('',#737,#736);
#739=CARTESIAN_POINT('',(80.,-6.,18.));
#740=VERTEX_POINT('',#739);
#741=EDGE_CURVE('E501',#732,#740,#738,.T.);
#742=ORIENTED_EDGE('',*,*,#741,.T.);
#743=EDGE_CURVE('E530',#665,#740,#583,.T.);
#744=ORIENTED_EDGE('',*,*,#743,.F.);
#745=ORIENTED_EDGE('',*,*,#666,.T.);
#746=EDGE_LOOP('',(#711,#717,#718,#726,#734,#742,#744,#745));
#747=FACE_BOUND('',#746,.T.);
#748=ADVANCED_FACE('F667',(#747),#703,.F.);
#749=CARTESIAN_POINT('',(80.,65.,18.));
#750=DIRECTION('',(0.,-1.,0.));
#751=DIRECTION('',(0.,0.,-1.));
#752=AXIS2_PLACEMENT_3D('',#749,#750,#751);
#753=PLANE('',#752);
#754=DIRECTION('',(-1.,0.,0.));
#755=VECTOR('',#754,1.);
#756=CARTESIAN_POINT('',(80.,65.,0.));
#757=LINE('',#756,#755);
#758=EDGE_CURVE('E542',#709,#603,#757,.T.);
#759=ORIENTED_EDGE('',*,*,#758,.T.);
#760=ORIENTED_EDGE('',*,*,#642,.F.);
#761=ORIENTED_EDGE('',*,*,#525,.F.);
#762=DIRECTION('',(0.,0.,-1.));
#763=VECTOR('',#762,1.);
#764=CARTESIAN_POINT('',(-6.5,65.,30.));
#765=LINE('',#764,#763);
#766=CARTESIAN_POINT('',(-6.5,65.,30.));
#767=VERTEX_POINT('',#766);
#768=EDGE_CURVE('E435',#767,#516,#765,.T.);
#769=ORIENTED_EDGE('',*,*,#768,.F.);
#770=DIRECTION('',(-1.,0.,0.));
#771=VECTOR('',#770,1.);
#772=CARTESIAN_POINT('',(6.5,65.,30.));
#773=LINE('',#772,#771);
#774=CARTESIAN_POINT('',(6.5,65.,30.));
#775=VERTEX_POINT('',#774);
#776=EDGE_CURVE('E429',#775,#767,#773,.T.);
#777=ORIENTED_EDGE('',*,*,#776,.F.);
#778=DIRECTION('',(0.,0.,-1.));
#779=VECTOR('',#778,1.);
#780=CARTESIAN_POINT('',(6.5,65.,30.));
#781=LINE('',#780,#779);
#782=EDGE_CURVE('E439',#775,#568,#781,.T.);
#783=ORIENTED_EDGE('',*,*,#782,.T.);
#784=ORIENTED_EDGE('',*,*,#588,.F.);
#785=ORIENTED_EDGE('',*,*,#716,.T.);
#786=EDGE_LOOP('',(#759,#760,#761,#769,#777,#783,#784,#785));
#787=FACE_BOUND('',#786,.T.);
#788=ADVANCED_FACE('F659',(#787),#753,.F.);
#789=CARTESIAN_POINT('',(49.4974746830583,-49.4974746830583,18.));
#790=DIRECTION('',(0.,0.,1.));
#791=DIRECTION('',(1.,0.,0.));
#792=AXIS2_PLACEMENT_3D('',#789,#790,#791);
#793=CIRCLE('',#792,6.);
#794=CARTESIAN_POINT('',(55.4974746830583,-49.4974746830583,18.));
#795=VERTEX_POINT('',#794);
#796=EDGE_CURVE('E1313',#795,#795,#793,.T.);
#797=ORIENTED_EDGE('',*,*,#796,.F.);
#798=EDGE_LOOP('',(#797));
#799=FACE_BOUND('',#798,.T.);
#800=CARTESIAN_POINT('',(65.,-50.,18.));
#801=DIRECTION('',(0.,0.,1.));
#802=DIRECTION('',(1.,0.,0.));
#803=AXIS2_PLACEMENT_3D('',#800,#801,#802);
#804=CIRCLE('',#803,4.5);
#805=CARTESIAN_POINT('',(69.5,-50.,18.));
#806=VERTEX_POINT('',#805);
#807=EDGE_CURVE('E268',#806,#806,#804,.T.);
#808=ORIENTED_EDGE('',*,*,#807,.F.);
#809=EDGE_LOOP('',(#808));
#810=FACE_BOUND('',#809,.T.);
#811=DIRECTION('',(0.,1.,0.));
#812=VECTOR('',#811,1.);
#813=CARTESIAN_POINT('',(6.75,-65.,18.));
#814=LINE('',#813,#812);
#815=EDGE_CURVE('E400',#669,#318,#814,.T.);
#816=ORIENTED_EDGE('',*,*,#815,.F.);
#817=ORIENTED_EDGE('',*,*,#670,.T.);
#818=ORIENTED_EDGE('',*,*,#743,.T.);
#819=DIRECTION('',(1.,0.,0.));
#820=VECTOR('',#819,1.);
#821=CARTESIAN_POINT('',(50.,-6.,18.));
#822=LINE('',#821,#820);
#823=EDGE_CURVE('E482',#324,#740,#822,.T.);
#824=ORIENTED_EDGE('',*,*,#823,.F.);
#825=ORIENTED_EDGE('',*,*,#325,.F.);
#826=EDGE_LOOP('',(#816,#817,#818,#824,#825));
#827=FACE_BOUND('',#826,.T.);
#828=ADVANCED_FACE('F653',(#799,#810,#827),#344,.T.);
#829=CARTESIAN_POINT('',(0.,0.,0.));
#830=DIRECTION('',(0.,0.,1.));
#831=DIRECTION('',(1.,0.,0.));
#832=AXIS2_PLACEMENT_3D('',#829,#830,#831);
#833=PLANE('',#832);
#834=CARTESIAN_POINT('',(38.802940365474,16.0727041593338,0.));
#835=DIRECTION('',(0.,0.,1.));
#836=DIRECTION('',(1.,0.,0.));
#837=AXIS2_PLACEMENT_3D('',#834,#835,#836);
#838=CIRCLE('',#837,2.5);
#839=CARTESIAN_POINT('',(41.302940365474,16.0727041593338,0.));
#840=VERTEX_POINT('',#839);
#841=EDGE_CURVE('E1292',#840,#840,#838,.T.);
#842=ORIENTED_EDGE('',*,*,#841,.T.);
#843=EDGE_LOOP('',(#842));
#844=FACE_BOUND('',#843,.T.);
#845=CARTESIAN_POINT('',(-38.8029403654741,-16.0727041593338,0.));
#846=DIRECTION('',(0.,0.,1.));
#847=DIRECTION('',(1.,0.,0.));
#848=AXIS2_PLACEMENT_3D('',#845,#846,#847);
#849=CIRCLE('',#848,2.5);
#850=CARTESIAN_POINT('',(-36.302940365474,-16.0727041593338,0.));
#851=VERTEX_POINT('',#850);
#852=EDGE_CURVE('E1279',#851,#851,#849,.T.);
#853=ORIENTED_EDGE('',*,*,#852,.T.);
#854=EDGE_LOOP('',(#853));
#855=FACE_BOUND('',#854,.T.);
#856=CARTESIAN_POINT('',(65.,-50.,0.));
#857=DIRECTION('',(0.,0.,1.));
#858=DIRECTION('',(1.,0.,0.));
#859=AXIS2_PLACEMENT_3D('',#856,#857,#858);
#860=CIRCLE('',#859,4.5);
#861=CARTESIAN_POINT('',(69.5,-50.,0.));
#862=VERTEX_POINT('',#861);
#863=EDGE_CURVE('E263',#862,#862,#860,.T.);
#864=ORIENTED_EDGE('',*,*,#863,.T.);
#865=EDGE_LOOP('',(#864));
#866=FACE_BOUND('',#865,.T.);
#867=CARTESIAN_POINT('',(-65.,-50.,0.));
#868=DIRECTION('',(0.,0.,1.));
#869=DIRECTION('',(1.,0.,0.));
#870=AXIS2_PLACEMENT_3D('',#867,#868,#869);
#871=CIRCLE('',#870,4.5);
#872=CARTESIAN_POINT('',(-60.5,-50.,0.));
#873=VERTEX_POINT('',#872);
#874=EDGE_CURVE('E258',#873,#873,#871,.T.);
#875=ORIENTED_EDGE('',*,*,#874,.T.);
#876=EDGE_LOOP('',(#875));
#877=FACE_BOUND('',#876,.T.);
#878=CARTESIAN_POINT('',(65.,50.,0.));
#879=DIRECTION('',(0.,0.,1.));
#880=DIRECTION('',(1.,0.,0.));
#881=AXIS2_PLACEMENT_3D('',#878,#879,#880);
#882=CIRCLE('',#881,4.5);
#883=CARTESIAN_POINT('',(69.5,50.,0.));
#884=VERTEX_POINT('',#883);
#885=EDGE_CURVE('E279',#884,#884,#882,.T.);
#886=ORIENTED_EDGE('',*,*,#885,.T.);
#887=EDGE_LOOP('',(#886));
#888=FACE_BOUND('',#887,.T.);
#889=CARTESIAN_POINT('',(-65.,50.,0.));
#890=DIRECTION('',(0.,0.,1.));
#891=DIRECTION('',(1.,0.,0.));
#892=AXIS2_PLACEMENT_3D('',#889,#890,#891);
#893=CIRCLE('',#892,4.5);
#894=CARTESIAN_POINT('',(-60.5,50.,0.));
#895=VERTEX_POINT('',#894);
#896=EDGE_CURVE('E266',#895,#895,#893,.T.);
#897=ORIENTED_EDGE('',*,*,#896,.T.);
#898=EDGE_LOOP('',(#897));
#899=FACE_BOUND('',#898,.T.);
#900=ORIENTED_EDGE('',*,*,#227,.T.);
#901=EDGE_LOOP('',(#900));
#902=FACE_BOUND('',#901,.T.);
#903=ORIENTED_EDGE('',*,*,#199,.T.);
#904=EDGE_LOOP('',(#903));
#905=FACE_BOUND('',#904,.T.);
#906=ORIENTED_EDGE('',*,*,#171,.T.);
#907=EDGE_LOOP('',(#906));
#908=FACE_BOUND('',#907,.T.);
#909=ORIENTED_EDGE('',*,*,#143,.T.);
#910=EDGE_LOOP('',(#909));
#911=FACE_BOUND('',#910,.T.);
#912=ORIENTED_EDGE('',*,*,#115,.T.);
#913=EDGE_LOOP('',(#912));
#914=FACE_BOUND('',#913,.T.);
#915=ORIENTED_EDGE('',*,*,#87,.T.);
#916=EDGE_LOOP('',(#915));
#917=FACE_BOUND('',#916,.T.);
#918=ORIENTED_EDGE('',*,*,#59,.T.);
#919=EDGE_LOOP('',(#918));
#920=FACE_BOUND('',#919,.T.);
#921=ORIENTED_EDGE('',*,*,#31,.T.);
#922=EDGE_LOOP('',(#921));
#923=FACE_BOUND('',#922,.T.);
#924=ORIENTED_EDGE('',*,*,#255,.T.);
#925=EDGE_LOOP('',(#924));
#926=FACE_BOUND('',#925,.T.);
#927=ORIENTED_EDGE('',*,*,#606,.F.);
#928=ORIENTED_EDGE('',*,*,#758,.F.);
#929=ORIENTED_EDGE('',*,*,#710,.F.);
#930=ORIENTED_EDGE('',*,*,#658,.F.);
#931=EDGE_LOOP('',(#927,#928,#929,#930));
#932=FACE_BOUND('',#931,.T.);
#933=ADVANCED_FACE('F649',(#844,#855,#866,#877,#888,#899,#902,#905,#908,#911,#914,#917,#920,
#923,#926,#932),#833,.F.);
#934=CARTESIAN_POINT('',(0.,0.,30.));
#935=DIRECTION('',(0.,0.,1.));
#936=DIRECTION('',(1.,0.,0.));
#937=AXIS2_PLACEMENT_3D('',#934,#935,#936);
#938=PLANE('',#937);
#939=CARTESIAN_POINT('',(-38.802940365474,16.0727041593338,30.));
#940=DIRECTION('',(0.,0.,1.));
#941=DIRECTION('',(1.,0.,0.));
#942=AXIS2_PLACEMENT_3D('',#939,#940,#941);
#943=CIRCLE('',#942,2.1);
#944=CARTESIAN_POINT('',(-36.702940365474,16.0727041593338,30.));
#945=VERTEX_POINT('',#944);
#946=EDGE_CURVE('E1281',#945,#945,#943,.T.);
#947=ORIENTED_EDGE('',*,*,#946,.F.);
#948=EDGE_LOOP('',(#947));
#949=FACE_BOUND('',#948,.T.);
#950=CARTESIAN_POINT('',(38.802940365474,16.0727041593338,30.));
#951=DIRECTION('',(0.,0.,1.));
#952=DIRECTION('',(1.,0.,0.));
#953=AXIS2_PLACEMENT_3D('',#950,#951,#952);
#954=CIRCLE('',#953,2.5);
#955=CARTESIAN_POINT('',(41.302940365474,16.0727041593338,30.));
#956=VERTEX_POINT('',#955);
#957=EDGE_CURVE('E1296',#956,#956,#954,.T.);
#958=ORIENTED_EDGE('',*,*,#957,.F.);
#959=EDGE_LOOP('',(#958));
#960=FACE_BOUND('',#959,.T.);
#961=CARTESIAN_POINT('',(-38.8029403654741,-16.0727041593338,30.));
#962=DIRECTION('',(0.,0.,1.));
#963=DIRECTION('',(1.,0.,0.));
#964=AXIS2_PLACEMENT_3D('',#961,#962,#963);
#965=CIRCLE('',#964,2.5);
#966=CARTESIAN_POINT('',(-36.302940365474,-16.0727041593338,30.));
#967=VERTEX_POINT('',#966);
#968=EDGE_CURVE('E1284',#967,#967,#965,.T.);
#969=ORIENTED_EDGE('',*,*,#968,.F.);
#970=EDGE_LOOP('',(#969));
#971=FACE_BOUND('',#970,.T.);
#972=CARTESIAN_POINT('',(46.,0.,30.));
#973=DIRECTION('',(0.,0.,1.));
#974=DIRECTION('',(1.,0.,0.));
#975=AXIS2_PLACEMENT_3D('',#972,#973,#974);
#976=CIRCLE('',#975,5.5);
#977=CARTESIAN_POINT('',(51.5,0.,30.));
#978=VERTEX_POINT('',#977);
#979=EDGE_CURVE('E300',#978,#978,#976,.T.);
#980=ORIENTED_EDGE('',*,*,#979,.F.);
#981=EDGE_LOOP('',(#980));
#982=FACE_BOUND('',#981,.T.);
#983=CARTESIAN_POINT('',(32.5269119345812,32.5269119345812,30.));
#984=DIRECTION('',(0.,0.,1.));
#985=DIRECTION('',(1.,0.,0.));
#986=AXIS2_PLACEMENT_3D('',#983,#984,#985);
#987=CIRCLE('',#986,5.5);
#988=CARTESIAN_POINT('',(38.0269119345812,32.5269119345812,30.));
#989=VERTEX_POINT('',#988);
#990=EDGE_CURVE('E297',#989,#989,#987,.T.);
#991=ORIENTED_EDGE('',*,*,#990,.F.);
#992=EDGE_LOOP('',(#991));
#993=FACE_BOUND('',#992,.T.);
#994=CARTESIAN_POINT('',(0.,46.,30.));
#995=DIRECTION('',(0.,0.,1.));
#996=DIRECTION('',(1.,0.,0.));
#997=AXIS2_PLACEMENT_3D('',#994,#995,#996);
#998=CIRCLE('',#997,5.5);
#999=CARTESIAN_POINT('',(5.5,46.,30.));
#1000=VERTEX_POINT('',#999);
#1001=EDGE_CURVE('E310',#1000,#1000,#998,.T.);
#1002=ORIENTED_EDGE('',*,*,#1001,.F.);
#1003=EDGE_LOOP('',(#1002));
#1004=FACE_BOUND('',#1003,.T.);
#1005=CARTESIAN_POINT('',(-32.5269119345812,32.5269119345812,30.));
#1006=DIRECTION('',(0.,0.,1.));
#1007=DIRECTION('',(1.,0.,0.));
#1008=AXIS2_PLACEMENT_3D('',#1005,#1006,#1007);
#1009=CIRCLE('',#1008,5.5);
#1010=CARTESIAN_POINT('',(-27.0269119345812,32.5269119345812,30.));
#1011=VERTEX_POINT('',#1010);
#1012=EDGE_CURVE('E313',#1011,#1011,#1009,.T.);
#1013=ORIENTED_EDGE('',*,*,#1012,.F.);
#1014=EDGE_LOOP('',(#1013));
#1015=FACE_BOUND('',#1014,.T.);
#1016=CARTESIAN_POINT('',(-46.,0.,30.));
#1017=DIRECTION('',(0.,0.,1.));
#1018=DIRECTION('',(1.,0.,0.));
#1019=AXIS2_PLACEMENT_3D('',#1016,#1017,#1018);
#1020=CIRCLE('',#1019,5.5);
#1021=CARTESIAN_POINT('',(-40.5,0.,30.));
#1022=VERTEX_POINT('',#1021);
#1023=EDGE_CURVE('E321',#1022,#1022,#1020,.T.);
#1024=ORIENTED_EDGE('',*,*,#1023,.F.);
#1025=EDGE_LOOP('',(#1024));
#1026=FACE_BOUND('',#1025,.T.);
#1027=CARTESIAN_POINT('',(-32.5269119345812,-32.5269119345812,30.));
#1028=DIRECTION('',(0.,0.,1.));
#1029=DIRECTION('',(1.,0.,0.));
#1030=AXIS2_PLACEMENT_3D('',#1027,#1028,#1029);
#1031=CIRCLE('',#1030,5.5);
#1032=CARTESIAN_POINT('',(-27.0269119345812,-32.5269119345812,30.));
#1033=VERTEX_POINT('',#1032);
#1034=EDGE_CURVE('E329',#1033,#1033,#1031,.T.);
#1035=ORIENTED_EDGE('',*,*,#1034,.F.);
#1036=EDGE_LOOP('',(#1035));
#1037=FACE_BOUND('',#1036,.T.);
#1038=CARTESIAN_POINT('',(0.,-46.,30.));
#1039=DIRECTION('',(0.,0.,1.));
#1040=DIRECTION('',(1.,0.,0.));
#1041=AXIS2_PLACEMENT_3D('',#1038,#1039,#1040);
#1042=CIRCLE('',#1041,5.5);
#1043=CARTESIAN_POINT('',(5.49999999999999,-46.,30.));
#1044=VERTEX_POINT('',#1043);
#1045=EDGE_CURVE('E333',#1044,#1044,#1042,.T.);
#1046=ORIENTED_EDGE('',*,*,#1045,.F.);
#1047=EDGE_LOOP('',(#1046));
#1048=FACE_BOUND('',#1047,.T.);
#1049=CARTESIAN_POINT('',(32.5269119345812,-32.5269119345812,30.));
#1050=DIRECTION('',(0.,0.,1.));
#1051=DIRECTION('',(1.,0.,0.));
#1052=AXIS2_PLACEMENT_3D('',#1049,#1050,#1051);
#1053=CIRCLE('',#1052,5.5);
#1054=CARTESIAN_POINT('',(38.0269119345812,-32.5269119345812,30.));
#1055=VERTEX_POINT('',#1054);
#1056=EDGE_CURVE('E342',#1055,#1055,#1053,.T.);
#1057=ORIENTED_EDGE('',*,*,#1056,.F.);
#1058=EDGE_LOOP('',(#1057));
#1059=FACE_BOUND('',#1058,.T.);
#1060=CARTESIAN_POINT('',(0.,0.,30.));
#1061=DIRECTION('',(0.,0.,1.));
#1062=DIRECTION('',(1.,0.,0.));
#1063=AXIS2_PLACEMENT_3D('',#1060,#1061,#1062);
#1064=CIRCLE('',#1063,36.);
#1065=CARTESIAN_POINT('',(36.,0.,30.));
#1066=VERTEX_POINT('',#1065);
#1067=EDGE_CURVE('E355',#1066,#1066,#1064,.T.);
#1068=ORIENTED_EDGE('',*,*,#1067,.F.);
#1069=EDGE_LOOP('',(#1068));
#1070=FACE_BOUND('',#1069,.T.);
#1071=ORIENTED_EDGE('',*,*,#293,.T.);
#1072=DIRECTION('',(0.,-1.,0.));
#1073=VECTOR('',#1072,1.);
#1074=CARTESIAN_POINT('',(-6.75,-50.,30.));
#1075=LINE('',#1074,#1073);
#1076=EDGE_CURVE('E394',#281,#685,#1075,.T.);
#1077=ORIENTED_EDGE('',*,*,#1076,.T.);
#1078=ORIENTED_EDGE('',*,*,#686,.T.);
#1079=DIRECTION('',(0.,1.,0.));
#1080=VECTOR('',#1079,1.);
#1081=CARTESIAN_POINT('',(6.75,-65.,30.));
#1082=LINE('',#1081,#1080);
#1083=EDGE_CURVE('E398',#677,#320,#1082,.T.);
#1084=ORIENTED_EDGE('',*,*,#1083,.T.);
#1085=ORIENTED_EDGE('',*,*,#335,.T.);
#1086=DIRECTION('',(1.,0.,0.));
#1087=VECTOR('',#1086,1.);
#1088=CARTESIAN_POINT('',(50.,-6.,30.));
#1089=LINE('',#1088,#1087);
#1090=EDGE_CURVE('E485',#332,#732,#1089,.T.);
#1091=ORIENTED_EDGE('',*,*,#1090,.T.);
#1092=ORIENTED_EDGE('',*,*,#733,.T.);
#1093=DIRECTION('',(-1.,0.,0.));
#1094=VECTOR('',#1093,1.);
#1095=CARTESIAN_POINT('',(80.,6.,30.));
#1096=LINE('',#1095,#1094);
#1097=EDGE_CURVE('E490',#724,#473,#1096,.T.);
#1098=ORIENTED_EDGE('',*,*,#1097,.T.);
#1099=ORIENTED_EDGE('',*,*,#474,.T.);
#1100=DIRECTION('',(0.,1.,0.));
#1101=VECTOR('',#1100,1.);
#1102=CARTESIAN_POINT('',(6.5,50.,30.));
#1103=LINE('',#1102,#1101);
#1104=EDGE_CURVE('E424',#467,#775,#1103,.T.);
#1105=ORIENTED_EDGE('',*,*,#1104,.T.);
#1106=ORIENTED_EDGE('',*,*,#776,.T.);
#1107=DIRECTION('',(0.,-1.,0.));
#1108=VECTOR('',#1107,1.);
#1109=CARTESIAN_POINT('',(-6.5,65.,30.));
#1110=LINE('',#1109,#1108);
#1111=EDGE_CURVE('E423',#767,#442,#1110,.T.);
#1112=ORIENTED_EDGE('',*,*,#1111,.T.);
#1113=ORIENTED_EDGE('',*,*,#457,.T.);
#1114=DIRECTION('',(-1.,0.,0.));
#1115=VECTOR('',#1114,1.);
#1116=CARTESIAN_POINT('',(-50.,6.25,30.));
#1117=LINE('',#1116,#1115);
#1118=EDGE_CURVE('E458',#454,#628,#1117,.T.);
#1119=ORIENTED_EDGE('',*,*,#1118,.T.);
#1120=ORIENTED_EDGE('',*,*,#629,.T.);
#1121=DIRECTION('',(1.,0.,0.));
#1122=VECTOR('',#1121,1.);
#1123=CARTESIAN_POINT('',(-80.,-6.25,30.));
#1124=LINE('',#1123,#1122);
#1125=EDGE_CURVE('E455',#620,#292,#1124,.T.);
#1126=ORIENTED_EDGE('',*,*,#1125,.T.);
#1127=EDGE_LOOP('',(#1071,#1077,#1078,#1084,#1085,#1091,#1092,#1098,#1099,#1105,#1106,#1112,
#1113,#1119,#1120,#1126));
#1128=FACE_BOUND('',#1127,.T.);
#1129=ADVANCED_FACE('F641',(#949,#960,#971,#982,#993,#1004,#1015,#1026,#1037,#1048,#1059,#1070,
#1128),#938,.T.);
#1130=CARTESIAN_POINT('',(50.,-6.,30.));
#1131=DIRECTION('',(0.,1.,0.));
#1132=DIRECTION('',(0.,0.,1.));
#1133=AXIS2_PLACEMENT_3D('',#1130,#1131,#1132);
#1134=PLANE('',#1133);
#1135=ORIENTED_EDGE('',*,*,#1090,.F.);
#1136=ORIENTED_EDGE('',*,*,#333,.T.);
#1137=ORIENTED_EDGE('',*,*,#823,.T.);
#1138=ORIENTED_EDGE('',*,*,#741,.F.);
#1139=EDGE_LOOP('',(#1135,#1136,#1137,#1138));
#1140=FACE_BOUND('',#1139,.T.);
#1141=ADVANCED_FACE('F639',(#1140),#1134,.F.);
#1142=CARTESIAN_POINT('',(80.,6.,30.));
#1143=DIRECTION('',(0.,-1.,0.));
#1144=DIRECTION('',(0.,0.,-1.));
#1145=AXIS2_PLACEMENT_3D('',#1142,#1143,#1144);
#1146=PLANE('',#1145);
#1147=ORIENTED_EDGE('',*,*,#578,.T.);
#1148=ORIENTED_EDGE('',*,*,#482,.T.);
#1149=ORIENTED_EDGE('',*,*,#1097,.F.);
#1150=ORIENTED_EDGE('',*,*,#725,.T.);
#1151=EDGE_LOOP('',(#1147,#1148,#1149,#1150));
#1152=FACE_BOUND('',#1151,.T.);
#1153=ADVANCED_FACE('F636',(#1152),#1146,.F.);
#1154=CARTESIAN_POINT('',(-80.,-6.25,30.));
#1155=DIRECTION('',(0.,1.,0.));
#1156=DIRECTION('',(0.,0.,1.));
#1157=AXIS2_PLACEMENT_3D('',#1154,#1155,#1156);
#1158=PLANE('',#1157);
#1159=ORIENTED_EDGE('',*,*,#416,.T.);
#1160=ORIENTED_EDGE('',*,*,#301,.T.);
#1161=ORIENTED_EDGE('',*,*,#1125,.F.);
#1162=ORIENTED_EDGE('',*,*,#621,.T.);
#1163=EDGE_LOOP('',(#1159,#1160,#1161,#1162));
#1164=FACE_BOUND('',#1163,.T.);
#1165=ADVANCED_FACE('F635',(#1164),#1158,.F.);
#1166=CARTESIAN_POINT('',(-50.,6.25,30.));
#1167=DIRECTION('',(0.,-1.,0.));
#1168=DIRECTION('',(0.,0.,-1.));
#1169=AXIS2_PLACEMENT_3D('',#1166,#1167,#1168);
#1170=PLANE('',#1169);
#1171=ORIENTED_EDGE('',*,*,#1118,.F.);
#1172=ORIENTED_EDGE('',*,*,#455,.T.);
#1173=ORIENTED_EDGE('',*,*,#535,.T.);
#1174=ORIENTED_EDGE('',*,*,#635,.F.);
#1175=EDGE_LOOP('',(#1171,#1172,#1173,#1174));
#1176=FACE_BOUND('',#1175,.T.);
#1177=ADVANCED_FACE('F628',(#1176),#1170,.F.);
#1178=CARTESIAN_POINT('',(-6.5,65.,30.));
#1179=DIRECTION('',(1.,0.,0.));
#1180=DIRECTION('',(0.,0.,-1.));
#1181=AXIS2_PLACEMENT_3D('',#1178,#1179,#1180);
#1182=PLANE('',#1181);
#1183=ORIENTED_EDGE('',*,*,#517,.T.);
#1184=ORIENTED_EDGE('',*,*,#443,.T.);
#1185=ORIENTED_EDGE('',*,*,#1111,.F.);
#1186=ORIENTED_EDGE('',*,*,#768,.T.);
#1187=EDGE_LOOP('',(#1183,#1184,#1185,#1186));
#1188=FACE_BOUND('',#1187,.T.);
#1189=ADVANCED_FACE('F624',(#1188),#1182,.F.);
#1190=CARTESIAN_POINT('',(6.5,50.,30.));
#1191=DIRECTION('',(-1.,0.,0.));
#1192=DIRECTION('',(0.,0.,1.));
#1193=AXIS2_PLACEMENT_3D('',#1190,#1191,#1192);
#1194=PLANE('',#1193);
#1195=ORIENTED_EDGE('',*,*,#1104,.F.);
#1196=ORIENTED_EDGE('',*,*,#470,.T.);
#1197=ORIENTED_EDGE('',*,*,#569,.T.);
#1198=ORIENTED_EDGE('',*,*,#782,.F.);
#1199=EDGE_LOOP('',(#1195,#1196,#1197,#1198));
#1200=FACE_BOUND('',#1199,.T.);
#1201=ADVANCED_FACE('F619',(#1200),#1194,.F.);
#1202=CARTESIAN_POINT('',(-6.75,-50.,30.));
#1203=DIRECTION('',(1.,0.,0.));
#1204=DIRECTION('',(0.,0.,-1.));
#1205=AXIS2_PLACEMENT_3D('',#1202,#1203,#1204);
#1206=PLANE('',#1205);
#1207=ORIENTED_EDGE('',*,*,#1076,.F.);
#1208=ORIENTED_EDGE('',*,*,#284,.T.);
#1209=ORIENTED_EDGE('',*,*,#407,.T.);
#1210=ORIENTED_EDGE('',*,*,#692,.F.);
#1211=EDGE_LOOP('',(#1207,#1208,#1209,#1210));
#1212=FACE_BOUND('',#1211,.T.);
#1213=ADVANCED_FACE('F618',(#1212),#1206,.F.);
#1214=CARTESIAN_POINT('',(6.75,-65.,30.));
#1215=DIRECTION('',(-1.,0.,0.));
#1216=DIRECTION('',(0.,0.,1.));
#1217=AXIS2_PLACEMENT_3D('',#1214,#1215,#1216);
#1218=PLANE('',#1217);
#1219=ORIENTED_EDGE('',*,*,#815,.T.);
#1220=ORIENTED_EDGE('',*,*,#321,.T.);
#1221=ORIENTED_EDGE('',*,*,#1083,.F.);
#1222=ORIENTED_EDGE('',*,*,#678,.T.);
#1223=EDGE_LOOP('',(#1219,#1220,#1221,#1222));
#1224=FACE_BOUND('',#1223,.T.);
#1225=ADVANCED_FACE('F602',(#1224),#1218,.F.);
#1226=CARTESIAN_POINT('',(0.,0.,26.));
#1227=DIRECTION('',(0.,0.,1.));
#1228=DIRECTION('',(1.,0.,0.));
#1229=AXIS2_PLACEMENT_3D('',#1226,#1227,#1228);
#1230=PLANE('',#1229);
#1231=CARTESIAN_POINT('',(0.,0.,26.));
#1232=DIRECTION('',(0.,0.,1.));
#1233=DIRECTION('',(1.,0.,0.));
#1234=AXIS2_PLACEMENT_3D('',#1231,#1232,#1233);
#1235=CIRCLE('',#1234,36.);
#1236=CARTESIAN_POINT('',(36.,0.,26.));
#1237=VERTEX_POINT('',#1236);
#1238=EDGE_CURVE('E382',#1237,#1237,#1235,.T.);
#1239=ORIENTED_EDGE('',*,*,#1238,.T.);
#1240=EDGE_LOOP('',(#1239));
#1241=FACE_BOUND('',#1240,.T.);
#1242=ORIENTED_EDGE('',*,*,#266,.T.);
#1243=EDGE_LOOP('',(#1242));
#1244=FACE_BOUND('',#1243,.T.);
#1245=ADVANCED_FACE('F596',(#1241,#1244),#1230,.T.);
#1246=CARTESIAN_POINT('',(0.,0.,26.));
#1247=DIRECTION('',(0.,0.,1.));
#1248=DIRECTION('',(1.,0.,0.));
#1249=AXIS2_PLACEMENT_3D('',#1246,#1247,#1248);
#1250=CYLINDRICAL_SURFACE('',#1249,36.);
#1251=ORIENTED_EDGE('',*,*,#1238,.F.);
#1252=EDGE_LOOP('',(#1251));
#1253=FACE_BOUND('',#1252,.T.);
#1254=ORIENTED_EDGE('',*,*,#1067,.T.);
#1255=EDGE_LOOP('',(#1254));
#1256=FACE_BOUND('',#1255,.T.);
#1257=ADVANCED_FACE('F601',(#1253,#1256),#1250,.F.);
#1258=CARTESIAN_POINT('',(46.,0.,25.));
#1259=DIRECTION('',(0.,0.,1.));
#1260=DIRECTION('',(1.,0.,0.));
#1261=AXIS2_PLACEMENT_3D('',#1258,#1259,#1260);
#1262=PLANE('',#1261);
#1263=CARTESIAN_POINT('',(46.,0.,25.));
#1264=DIRECTION('',(0.,0.,1.));
#1265=DIRECTION('',(1.,0.,0.));
#1266=AXIS2_PLACEMENT_3D('',#1263,#1264,#1265);
#1267=CIRCLE('',#1266,5.5);
#1268=CARTESIAN_POINT('',(51.5,0.,25.));
#1269=VERTEX_POINT('',#1268);
#1270=EDGE_CURVE('E292',#1269,#1269,#1267,.T.);
#1271=ORIENTED_EDGE('',*,*,#1270,.T.);
#1272=EDGE_LOOP('',(#1271));
#1273=FACE_BOUND('',#1272,.T.);
#1274=ORIENTED_EDGE('',*,*,#238,.T.);
#1275=EDGE_LOOP('',(#1274));
#1276=FACE_BOUND('',#1275,.T.);
#1277=ADVANCED_FACE('F607',(#1273,#1276),#1262,.T.);
#1278=CARTESIAN_POINT('',(46.,0.,25.));
#1279=DIRECTION('',(0.,0.,1.));
#1280=DIRECTION('',(1.,0.,0.));
#1281=AXIS2_PLACEMENT_3D('',#1278,#1279,#1280);
#1282=CYLINDRICAL_SURFACE('',#1281,5.5);
#1283=ORIENTED_EDGE('',*,*,#1270,.F.);
#1284=EDGE_LOOP('',(#1283));
#1285=FACE_BOUND('',#1284,.T.);
#1286=ORIENTED_EDGE('',*,*,#979,.T.);
#1287=EDGE_LOOP('',(#1286));
#1288=FACE_BOUND('',#1287,.T.);
#1289=ADVANCED_FACE('F850',(#1285,#1288),#1282,.F.);
#1290=CARTESIAN_POINT('',(32.5269119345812,32.5269119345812,25.));
#1291=DIRECTION('',(0.,0.,1.));
#1292=DIRECTION('',(1.,0.,0.));
#1293=AXIS2_PLACEMENT_3D('',#1290,#1291,#1292);
#1294=PLANE('',#1293);
#1295=CARTESIAN_POINT('',(32.5269119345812,32.5269119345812,25.));
#1296=DIRECTION('',(0.,0.,1.));
#1297=DIRECTION('',(1.,0.,0.));
#1298=AXIS2_PLACEMENT_3D('',#1295,#1296,#1297);
#1299=CIRCLE('',#1298,5.5);
#1300=CARTESIAN_POINT('',(38.0269119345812,32.5269119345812,25.));
#1301=VERTEX_POINT('',#1300);
#1302=EDGE_CURVE('E303',#1301,#1301,#1299,.T.);
#1303=ORIENTED_EDGE('',*,*,#1302,.T.);
#1304=EDGE_LOOP('',(#1303));
#1305=FACE_BOUND('',#1304,.T.);
#1306=ORIENTED_EDGE('',*,*,#210,.T.);
#1307=EDGE_LOOP('',(#1306));
#1308=FACE_BOUND('',#1307,.T.);
#1309=ADVANCED_FACE('F860',(#1305,#1308),#1294,.T.);
#1310=CARTESIAN_POINT('',(32.5269119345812,32.5269119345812,25.));
#1311=DIRECTION('',(0.,0.,1.));
#1312=DIRECTION('',(1.,0.,0.));
#1313=AXIS2_PLACEMENT_3D('',#1310,#1311,#1312);
#1314=CYLINDRICAL_SURFACE('',#1313,5.5);
#1315=ORIENTED_EDGE('',*,*,#1302,.F.);
#1316=EDGE_LOOP('',(#1315));
#1317=FACE_BOUND('',#1316,.T.);
#1318=ORIENTED_EDGE('',*,*,#990,.T.);
#1319=EDGE_LOOP('',(#1318));
#1320=FACE_BOUND('',#1319,.T.);
#1321=ADVANCED_FACE('F870',(#1317,#1320),#1314,.F.);
#1322=CARTESIAN_POINT('',(0.,46.,25.));
#1323=DIRECTION('',(0.,0.,1.));
#1324=DIRECTION('',(1.,0.,0.));
#1325=AXIS2_PLACEMENT_3D('',#1322,#1323,#1324);
#1326=PLANE('',#1325);
#1327=CARTESIAN_POINT('',(0.,46.,25.));
#1328=DIRECTION('',(0.,0.,1.));
#1329=DIRECTION('',(1.,0.,0.));
#1330=AXIS2_PLACEMENT_3D('',#1327,#1328,#1329);
#1331=CIRCLE('',#1330,5.5);
#1332=CARTESIAN_POINT('',(5.5,46.,25.));
#1333=VERTEX_POINT('',#1332);
#1334=EDGE_CURVE('E309',#1333,#1333,#1331,.T.);
#1335=ORIENTED_EDGE('',*,*,#1334,.T.);
#1336=EDGE_LOOP('',(#1335));
#1337=FACE_BOUND('',#1336,.T.);
#1338=ORIENTED_EDGE('',*,*,#182,.T.);
#1339=EDGE_LOOP('',(#1338));
#1340=FACE_BOUND('',#1339,.T.);
#1341=ADVANCED_FACE('F877',(#1337,#1340),#1326,.T.);
#1342=CARTESIAN_POINT('',(0.,46.,25.));
#1343=DIRECTION('',(0.,0.,1.));
#1344=DIRECTION('',(1.,0.,0.));
#1345=AXIS2_PLACEMENT_3D('',#1342,#1343,#1344);
#1346=CYLINDRICAL_SURFACE('',#1345,5.5);
#1347=ORIENTED_EDGE('',*,*,#1334,.F.);
#1348=EDGE_LOOP('',(#1347));
#1349=FACE_BOUND('',#1348,.T.);
#1350=ORIENTED_EDGE('',*,*,#1001,.T.);
#1351=EDGE_LOOP('',(#1350));
#1352=FACE_BOUND('',#1351,.T.);
#1353=ADVANCED_FACE('F890',(#1349,#1352),#1346,.F.);
#1354=CARTESIAN_POINT('',(-32.5269119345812,32.5269119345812,25.));
#1355=DIRECTION('',(0.,0.,1.));
#1356=DIRECTION('',(1.,0.,0.));
#1357=AXIS2_PLACEMENT_3D('',#1354,#1355,#1356);
#1358=PLANE('',#1357);
#1359=CARTESIAN_POINT('',(-32.5269119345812,32.5269119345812,25.));
#1360=DIRECTION('',(0.,0.,1.));
#1361=DIRECTION('',(1.,0.,0.));
#1362=AXIS2_PLACEMENT_3D('',#1359,#1360,#1361);
#1363=CIRCLE('',#1362,5.5);
#1364=CARTESIAN_POINT('',(-27.0269119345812,32.5269119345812,25.));
#1365=VERTEX_POINT('',#1364);
#1366=EDGE_CURVE('E320',#1365,#1365,#1363,.T.);
#1367=ORIENTED_EDGE('',*,*,#1366,.T.);
#1368=EDGE_LOOP('',(#1367));
#1369=FACE_BOUND('',#1368,.T.);
#1370=ORIENTED_EDGE('',*,*,#154,.T.);
#1371=EDGE_LOOP('',(#1370));
#1372=FACE_BOUND('',#1371,.T.);
#1373=ADVANCED_FACE('F900',(#1369,#1372),#1358,.T.);
#1374=CARTESIAN_POINT('',(-32.5269119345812,32.5269119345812,25.));
#1375=DIRECTION('',(0.,0.,1.));
#1376=DIRECTION('',(1.,0.,0.));
#1377=AXIS2_PLACEMENT_3D('',#1374,#1375,#1376);
#1378=CYLINDRICAL_SURFACE('',#1377,5.5);
#1379=ORIENTED_EDGE('',*,*,#1366,.F.);
#1380=EDGE_LOOP('',(#1379));
#1381=FACE_BOUND('',#1380,.T.);
#1382=ORIENTED_EDGE('',*,*,#1012,.T.);
#1383=EDGE_LOOP('',(#1382));
#1384=FACE_BOUND('',#1383,.T.);
#1385=ADVANCED_FACE('F907',(#1381,#1384),#1378,.F.);
#1386=CARTESIAN_POINT('',(-46.,0.,25.));
#1387=DIRECTION('',(0.,0.,1.));
#1388=DIRECTION('',(1.,0.,0.));
#1389=AXIS2_PLACEMENT_3D('',#1386,#1387,#1388);
#1390=PLANE('',#1389);
#1391=CARTESIAN_POINT('',(-46.,0.,25.));
#1392=DIRECTION('',(0.,0.,1.));
#1393=DIRECTION('',(1.,0.,0.));
#1394=AXIS2_PLACEMENT_3D('',#1391,#1392,#1393);
#1395=CIRCLE('',#1394,5.5);
#1396=CARTESIAN_POINT('',(-40.5,0.,25.));
#1397=VERTEX_POINT('',#1396);
#1398=EDGE_CURVE('E323',#1397,#1397,#1395,.T.);
#1399=ORIENTED_EDGE('',*,*,#1398,.T.);
#1400=EDGE_LOOP('',(#1399));
#1401=FACE_BOUND('',#1400,.T.);
#1402=ORIENTED_EDGE('',*,*,#126,.T.);
#1403=EDGE_LOOP('',(#1402));
#1404=FACE_BOUND('',#1403,.T.);
#1405=ADVANCED_FACE('F920',(#1401,#1404),#1390,.T.);
#1406=CARTESIAN_POINT('',(-46.,0.,25.));
#1407=DIRECTION('',(0.,0.,1.));
#1408=DIRECTION('',(1.,0.,0.));
#1409=AXIS2_PLACEMENT_3D('',#1406,#1407,#1408);
#1410=CYLINDRICAL_SURFACE('',#1409,5.5);
#1411=ORIENTED_EDGE('',*,*,#1398,.F.);
#1412=EDGE_LOOP('',(#1411));
#1413=FACE_BOUND('',#1412,.T.);
#1414=ORIENTED_EDGE('',*,*,#1023,.T.);
#1415=EDGE_LOOP('',(#1414));
#1416=FACE_BOUND('',#1415,.T.);
#1417=ADVANCED_FACE('F927',(#1413,#1416),#1410,.F.);
#1418=CARTESIAN_POINT('',(-32.5269119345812,-32.5269119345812,25.));
#1419=DIRECTION('',(0.,0.,1.));
#1420=DIRECTION('',(1.,0.,0.));
#1421=AXIS2_PLACEMENT_3D('',#1418,#1419,#1420);
#1422=PLANE('',#1421);
#1423=CARTESIAN_POINT('',(-32.5269119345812,-32.5269119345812,25.));
#1424=DIRECTION('',(0.,0.,1.));
#1425=DIRECTION('',(1.,0.,0.));
#1426=AXIS2_PLACEMENT_3D('',#1423,#1424,#1425);
#1427=CIRCLE('',#1426,5.5);
#1428=CARTESIAN_POINT('',(-27.0269119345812,-32.5269119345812,25.));
#1429=VERTEX_POINT('',#1428);
#1430=EDGE_CURVE('E332',#1429,#1429,#1427,.T.);
#1431=ORIENTED_EDGE('',*,*,#1430,.T.);
#1432=EDGE_LOOP('',(#1431));
#1433=FACE_BOUND('',#1432,.T.);
#1434=ORIENTED_EDGE('',*,*,#98,.T.);
#1435=EDGE_LOOP('',(#1434));
#1436=FACE_BOUND('',#1435,.T.);
#1437=ADVANCED_FACE('F940',(#1433,#1436),#1422,.T.);
#1438=CARTESIAN_POINT('',(-32.5269119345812,-32.5269119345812,25.));
#1439=DIRECTION('',(0.,0.,1.));
#1440=DIRECTION('',(1.,0.,0.));
#1441=AXIS2_PLACEMENT_3D('',#1438,#1439,#1440);
#1442=CYLINDRICAL_SURFACE('',#1441,5.5);
#1443=ORIENTED_EDGE('',*,*,#1430,.F.);
#1444=EDGE_LOOP('',(#1443));
#1445=FACE_BOUND('',#1444,.T.);
#1446=ORIENTED_EDGE('',*,*,#1034,.T.);
#1447=EDGE_LOOP('',(#1446));
#1448=FACE_BOUND('',#1447,.T.);
#1449=ADVANCED_FACE('F950',(#1445,#1448),#1442,.F.);
#1450=CARTESIAN_POINT('',(0.,-46.,25.));
#1451=DIRECTION('',(0.,0.,1.));
#1452=DIRECTION('',(1.,0.,0.));
#1453=AXIS2_PLACEMENT_3D('',#1450,#1451,#1452);
#1454=PLANE('',#1453);
#1455=CARTESIAN_POINT('',(0.,-46.,25.));
#1456=DIRECTION('',(0.,0.,1.));
#1457=DIRECTION('',(1.,0.,0.));
#1458=AXIS2_PLACEMENT_3D('',#1455,#1456,#1457);
#1459=CIRCLE('',#1458,5.5);
#1460=CARTESIAN_POINT('',(5.49999999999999,-46.,25.));
#1461=VERTEX_POINT('',#1460);
#1462=EDGE_CURVE('E336',#1461,#1461,#1459,.T.);
#1463=ORIENTED_EDGE('',*,*,#1462,.T.);
#1464=EDGE_LOOP('',(#1463));
#1465=FACE_BOUND('',#1464,.T.);
#1466=ORIENTED_EDGE('',*,*,#70,.T.);
#1467=EDGE_LOOP('',(#1466));
#1468=FACE_BOUND('',#1467,.T.);
#1469=ADVANCED_FACE('F960',(#1465,#1468),#1454,.T.);
#1470=CARTESIAN_POINT('',(0.,-46.,25.));
#1471=DIRECTION('',(0.,0.,1.));
#1472=DIRECTION('',(1.,0.,0.));
#1473=AXIS2_PLACEMENT_3D('',#1470,#1471,#1472);
#1474=CYLINDRICAL_SURFACE('',#1473,5.5);
#1475=ORIENTED_EDGE('',*,*,#1462,.F.);
#1476=EDGE_LOOP('',(#1475));
#1477=FACE_BOUND('',#1476,.T.);
#1478=ORIENTED_EDGE('',*,*,#1045,.T.);
#1479=EDGE_LOOP('',(#1478));
#1480=FACE_BOUND('',#1479,.T.);
#1481=ADVANCED_FACE('F970',(#1477,#1480),#1474,.F.);
#1482=CARTESIAN_POINT('',(32.5269119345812,-32.5269119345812,25.));
#1483=DIRECTION('',(0.,0.,1.));
#1484=DIRECTION('',(1.,0.,0.));
#1485=AXIS2_PLACEMENT_3D('',#1482,#1483,#1484);
#1486=PLANE('',#1485);
#1487=CARTESIAN_POINT('',(32.5269119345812,-32.5269119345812,25.));
#1488=DIRECTION('',(0.,0.,1.));
#1489=DIRECTION('',(1.,0.,0.));
#1490=AXIS2_PLACEMENT_3D('',#1487,#1488,#1489);
#1491=CIRCLE('',#1490,5.5);
#1492=CARTESIAN_POINT('',(38.0269119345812,-32.5269119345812,25.));
#1493=VERTEX_POINT('',#1492);
#1494=EDGE_CURVE('E285',#1493,#1493,#1491,.T.);
#1495=ORIENTED_EDGE('',*,*,#1494,.T.);
#1496=EDGE_LOOP('',(#1495));
#1497=FACE_BOUND('',#1496,.T.);
#1498=ORIENTED_EDGE('',*,*,#42,.T.);
#1499=EDGE_LOOP('',(#1498));
#1500=FACE_BOUND('',#1499,.T.);
#1501=ADVANCED_FACE('F584',(#1497,#1500),#1486,.T.);
#1502=CARTESIAN_POINT('',(32.5269119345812,-32.5269119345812,25.));
#1503=DIRECTION('',(0.,0.,1.));
#1504=DIRECTION('',(1.,0.,0.));
#1505=AXIS2_PLACEMENT_3D('',#1502,#1503,#1504);
#1506=CYLINDRICAL_SURFACE('',#1505,5.5);
#1507=ORIENTED_EDGE('',*,*,#1494,.F.);
#1508=EDGE_LOOP('',(#1507));
#1509=FACE_BOUND('',#1508,.T.);
#1510=ORIENTED_EDGE('',*,*,#1056,.T.);
#1511=EDGE_LOOP('',(#1510));
#1512=FACE_BOUND('',#1511,.T.);
#1513=ADVANCED_FACE('F987',(#1509,#1512),#1506,.F.);
#1514=CARTESIAN_POINT('',(-65.,50.,0.));
#1515=DIRECTION('',(0.,0.,1.));
#1516=DIRECTION('',(1.,0.,0.));
#1517=AXIS2_PLACEMENT_3D('',#1514,#1515,#1516);
#1518=CYLINDRICAL_SURFACE('',#1517,4.5);
#1519=ORIENTED_EDGE('',*,*,#896,.F.);
#1520=EDGE_LOOP('',(#1519));
#1521=FACE_BOUND('',#1520,.T.);
#1522=ORIENTED_EDGE('',*,*,#507,.T.);
#1523=EDGE_LOOP('',(#1522));
#1524=FACE_BOUND('',#1523,.T.);
#1525=ADVANCED_FACE('F995',(#1521,#1524),#1518,.F.);
#1526=CARTESIAN_POINT('',(65.,50.,0.));
#1527=DIRECTION('',(0.,0.,1.));
#1528=DIRECTION('',(1.,0.,0.));
#1529=AXIS2_PLACEMENT_3D('',#1526,#1527,#1528);
#1530=CYLINDRICAL_SURFACE('',#1529,4.5);
#1531=ORIENTED_EDGE('',*,*,#885,.F.);
#1532=EDGE_LOOP('',(#1531));
#1533=FACE_BOUND('',#1532,.T.);
#1534=ORIENTED_EDGE('',*,*,#559,.T.);
#1535=EDGE_LOOP('',(#1534));
#1536=FACE_BOUND('',#1535,.T.);
#1537=ADVANCED_FACE('F1003',(#1533,#1536),#1530,.F.);
#1538=CARTESIAN_POINT('',(-65.,-50.,0.));
#1539=DIRECTION('',(0.,0.,1.));
#1540=DIRECTION('',(1.,0.,0.));
#1541=AXIS2_PLACEMENT_3D('',#1538,#1539,#1540);
#1542=CYLINDRICAL_SURFACE('',#1541,4.5);
#1543=ORIENTED_EDGE('',*,*,#874,.F.);
#1544=EDGE_LOOP('',(#1543));
#1545=FACE_BOUND('',#1544,.T.);
#1546=ORIENTED_EDGE('',*,*,#397,.T.);
#1547=EDGE_LOOP('',(#1546));
#1548=FACE_BOUND('',#1547,.T.);
#1549=ADVANCED_FACE('F1012',(#1545,#1548),#1542,.F.);
#1550=CARTESIAN_POINT('',(65.,-50.,0.));
#1551=DIRECTION('',(0.,0.,1.));
#1552=DIRECTION('',(1.,0.,0.));
#1553=AXIS2_PLACEMENT_3D('',#1550,#1551,#1552);
#1554=CYLINDRICAL_SURFACE('',#1553,4.5);
#1555=ORIENTED_EDGE('',*,*,#863,.F.);
#1556=EDGE_LOOP('',(#1555));
#1557=FACE_BOUND('',#1556,.T.);
#1558=ORIENTED_EDGE('',*,*,#807,.T.);
#1559=EDGE_LOOP('',(#1558));
#1560=FACE_BOUND('',#1559,.T.);
#1561=ADVANCED_FACE('F1024',(#1557,#1560),#1554,.F.);
#1562=CARTESIAN_POINT('',(-74.,-14.,10.));
#1563=DIRECTION('',(-1.,0.,0.));
#1564=DIRECTION('',(0.,0.,1.));
#1565=AXIS2_PLACEMENT_3D('',#1562,#1563,#1564);
#1566=PLANE('',#1565);
#1567=ORIENTED_EDGE('',*,*,#364,.T.);
#1568=DIRECTION('',(0.,0.,1.));
#1569=VECTOR('',#1568,1.);
#1570=CARTESIAN_POINT('',(-74.,-42.,10.));
#1571=LINE('',#1570,#1569);
#1572=CARTESIAN_POINT('',(-74.,-42.,10.));
#1573=VERTEX_POINT('',#1572);
#1574=EDGE_CURVE('E211',#1573,#363,#1571,.T.);
#1575=ORIENTED_EDGE('',*,*,#1574,.F.);
#1576=DIRECTION('',(0.,-1.,0.));
#1577=VECTOR('',#1576,1.);
#1578=CARTESIAN_POINT('',(-74.,-14.,10.));
#1579=LINE('',#1578,#1577);
#1580=CARTESIAN_POINT('',(-74.,-14.,10.));
#1581=VERTEX_POINT('',#1580);
#1582=EDGE_CURVE('E215',#1581,#1573,#1579,.T.);
#1583=ORIENTED_EDGE('',*,*,#1582,.F.);
#1584=DIRECTION('',(0.,0.,1.));
#1585=VECTOR('',#1584,1.);
#1586=CARTESIAN_POINT('',(-74.,-14.,10.));
#1587=LINE('',#1586,#1585);
#1588=EDGE_CURVE('E256',#1581,#361,#1587,.T.);
#1589=ORIENTED_EDGE('',*,*,#1588,.T.);
#1590=EDGE_LOOP('',(#1567,#1575,#1583,#1589));
#1591=FACE_BOUND('',#1590,.T.);
#1592=ADVANCED_FACE('F214',(#1591),#1566,.F.);
#1593=CARTESIAN_POINT('',(-58.,-14.,10.));
#1594=DIRECTION('',(0.,1.,0.));
#1595=DIRECTION('',(0.,0.,1.));
#1596=AXIS2_PLACEMENT_3D('',#1593,#1594,#1595);
#1597=PLANE('',#1596);
#1598=ORIENTED_EDGE('',*,*,#372,.T.);
#1599=ORIENTED_EDGE('',*,*,#1588,.F.);
#1600=DIRECTION('',(-1.,0.,0.));
#1601=VECTOR('',#1600,1.);
#1602=CARTESIAN_POINT('',(-58.,-14.,10.));
#1603=LINE('',#1602,#1601);
#1604=CARTESIAN_POINT('',(-58.,-14.,10.));
#1605=VERTEX_POINT('',#1604);
#1606=EDGE_CURVE('E225',#1605,#1581,#1603,.T.);
#1607=ORIENTED_EDGE('',*,*,#1606,.F.);
#1608=DIRECTION('',(0.,0.,1.));
#1609=VECTOR('',#1608,1.);
#1610=CARTESIAN_POINT('',(-58.,-14.,10.));
#1611=LINE('',#1610,#1609);
#1612=EDGE_CURVE('E260',#1605,#371,#1611,.T.);
#1613=ORIENTED_EDGE('',*,*,#1612,.T.);
#1614=EDGE_LOOP('',(#1598,#1599,#1607,#1613));
#1615=FACE_BOUND('',#1614,.T.);
#1616=ADVANCED_FACE('F1041',(#1615),#1597,.F.);
#1617=CARTESIAN_POINT('',(-58.,-42.,10.));
#1618=DIRECTION('',(1.,0.,0.));
#1619=DIRECTION('',(0.,0.,-1.));
#1620=AXIS2_PLACEMENT_3D('',#1617,#1618,#1619);
#1621=PLANE('',#1620);
#1622=ORIENTED_EDGE('',*,*,#380,.T.);
#1623=ORIENTED_EDGE('',*,*,#1612,.F.);
#1624=DIRECTION('',(0.,1.,0.));
#1625=VECTOR('',#1624,1.);
#1626=CARTESIAN_POINT('',(-58.,-42.,10.));
#1627=LINE('',#1626,#1625);
#1628=CARTESIAN_POINT('',(-58.,-42.,10.));
#1629=VERTEX_POINT('',#1628);
#1630=EDGE_CURVE('E233',#1629,#1605,#1627,.T.);
#1631=ORIENTED_EDGE('',*,*,#1630,.F.);
#1632=DIRECTION('',(0.,0.,1.));
#1633=VECTOR('',#1632,1.);
#1634=CARTESIAN_POINT('',(-58.,-42.,10.));
#1635=LINE('',#1634,#1633);
#1636=EDGE_CURVE('E222',#1629,#379,#1635,.T.);
#1637=ORIENTED_EDGE('',*,*,#1636,.T.);
#1638=EDGE_LOOP('',(#1622,#1623,#1631,#1637));
#1639=FACE_BOUND('',#1638,.T.);
#1640=ADVANCED_FACE('F1054',(#1639),#1621,.F.);
#1641=CARTESIAN_POINT('',(-74.,-42.,10.));
#1642=DIRECTION('',(0.,-1.,0.));
#1643=DIRECTION('',(0.,0.,-1.));
#1644=AXIS2_PLACEMENT_3D('',#1641,#1642,#1643);
#1645=PLANE('',#1644);
#1646=ORIENTED_EDGE('',*,*,#386,.T.);
#1647=ORIENTED_EDGE('',*,*,#1636,.F.);
#1648=DIRECTION('',(1.,0.,0.));
#1649=VECTOR('',#1648,1.);
#1650=CARTESIAN_POINT('',(-74.,-42.,10.));
#1651=LINE('',#1650,#1649);
#1652=EDGE_CURVE('E223',#1573,#1629,#1651,.T.);
#1653=ORIENTED_EDGE('',*,*,#1652,.F.);
#1654=ORIENTED_EDGE('',*,*,#1574,.T.);
#1655=EDGE_LOOP('',(#1646,#1647,#1653,#1654));
#1656=FACE_BOUND('',#1655,.T.);
#1657=ADVANCED_FACE('F228',(#1656),#1645,.F.);
#1658=CARTESIAN_POINT('',(0.,0.,10.));
#1659=DIRECTION('',(0.,0.,1.));
#1660=DIRECTION('',(1.,0.,0.));
#1661=AXIS2_PLACEMENT_3D('',#1658,#1659,#1660);
#1662=PLANE('',#1661);
#1663=ORIENTED_EDGE('',*,*,#1582,.T.);
#1664=ORIENTED_EDGE('',*,*,#1652,.T.);
#1665=ORIENTED_EDGE('',*,*,#1630,.T.);
#1666=ORIENTED_EDGE('',*,*,#1606,.T.);
#1667=EDGE_LOOP('',(#1663,#1664,#1665,#1666));
#1668=FACE_BOUND('',#1667,.T.);
#1669=ADVANCED_FACE('F231',(#1668),#1662,.T.);
#1670=CARTESIAN_POINT('',(49.4974746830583,-49.4974746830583,10.));
#1671=DIRECTION('',(0.,0.,1.));
#1672=DIRECTION('',(1.,0.,0.));
#1673=AXIS2_PLACEMENT_3D('',#1670,#1671,#1672);
#1674=CYLINDRICAL_SURFACE('',#1673,6.);
#1675=CARTESIAN_POINT('',(49.4974746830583,-49.4974746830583,10.));
#1676=DIRECTION('',(0.,0.,1.));
#1677=DIRECTION('',(1.,0.,0.));
#1678=AXIS2_PLACEMENT_3D('',#1675,#1676,#1677);
#1679=CIRCLE('',#1678,6.);
#1680=CARTESIAN_POINT('',(55.4974746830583,-49.4974746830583,10.));
#1681=VERTEX_POINT('',#1680);
#1682=EDGE_CURVE('E1293',#1681,#1681,#1679,.T.);
#1683=ORIENTED_EDGE('',*,*,#1682,.F.);
#1684=EDGE_LOOP('',(#1683));
#1685=FACE_BOUND('',#1684,.T.);
#1686=ORIENTED_EDGE('',*,*,#796,.T.);
#1687=EDGE_LOOP('',(#1686));
#1688=FACE_BOUND('',#1687,.T.);
#1689=ADVANCED_FACE('F1077',(#1685,#1688),#1674,.F.);
#1690=CARTESIAN_POINT('',(49.4974746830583,-49.4974746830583,10.));
#1691=DIRECTION('',(0.,0.,1.));
#1692=DIRECTION('',(1.,0.,0.));
#1693=AXIS2_PLACEMENT_3D('',#1690,#1691,#1692);
#1694=PLANE('',#1693);
#1695=ORIENTED_EDGE('',*,*,#1682,.T.);
#1696=EDGE_LOOP('',(#1695));
#1697=FACE_BOUND('',#1696,.T.);
#1698=ADVANCED_FACE('F1117',(#1697),#1694,.T.);
#1699=CARTESIAN_POINT('',(49.4974746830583,49.4974746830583,10.));
#1700=DIRECTION('',(0.,0.,1.));
#1701=DIRECTION('',(1.,0.,0.));
#1702=AXIS2_PLACEMENT_3D('',#1699,#1700,#1701);
#1703=CYLINDRICAL_SURFACE('',#1702,6.);
#1704=CARTESIAN_POINT('',(49.4974746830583,49.4974746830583,10.));
#1705=DIRECTION('',(0.,0.,1.));
#1706=DIRECTION('',(1.,0.,0.));
#1707=AXIS2_PLACEMENT_3D('',#1704,#1705,#1706);
#1708=CIRCLE('',#1707,6.);
#1709=CARTESIAN_POINT('',(55.4974746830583,49.4974746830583,10.));
#1710=VERTEX_POINT('',#1709);
#1711=EDGE_CURVE('E255',#1710,#1710,#1708,.T.);
#1712=ORIENTED_EDGE('',*,*,#1711,.F.);
#1713=EDGE_LOOP('',(#1712));
#1714=FACE_BOUND('',#1713,.T.);
#1715=ORIENTED_EDGE('',*,*,#548,.T.);
#1716=EDGE_LOOP('',(#1715));
#1717=FACE_BOUND('',#1716,.T.);
#1718=ADVANCED_FACE('F1130',(#1714,#1717),#1703,.F.);
#1719=CARTESIAN_POINT('',(49.4974746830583,49.4974746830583,10.));
#1720=DIRECTION('',(0.,0.,1.));
#1721=DIRECTION('',(1.,0.,0.));
#1722=AXIS2_PLACEMENT_3D('',#1719,#1720,#1721);
#1723=PLANE('',#1722);
#1724=ORIENTED_EDGE('',*,*,#1711,.T.);
#1725=EDGE_LOOP('',(#1724));
#1726=FACE_BOUND('',#1725,.T.);
#1727=ADVANCED_FACE('F1137',(#1726),#1723,.T.);
#1728=CARTESIAN_POINT('',(-49.4974746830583,49.4974746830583,10.));
#1729=DIRECTION('',(0.,0.,1.));
#1730=DIRECTION('',(1.,0.,0.));
#1731=AXIS2_PLACEMENT_3D('',#1728,#1729,#1730);
#1732=CYLINDRICAL_SURFACE('',#1731,6.);
#1733=CARTESIAN_POINT('',(-49.4974746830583,49.4974746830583,10.));
#1734=DIRECTION('',(0.,0.,1.));
#1735=DIRECTION('',(1.,0.,0.));
#1736=AXIS2_PLACEMENT_3D('',#1733,#1734,#1735);
#1737=CIRCLE('',#1736,6.);
#1738=CARTESIAN_POINT('',(-43.4974746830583,49.4974746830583,10.));
#1739=VERTEX_POINT('',#1738);
#1740=EDGE_CURVE('E1301',#1739,#1739,#1737,.T.);
#1741=ORIENTED_EDGE('',*,*,#1740,.F.);
#1742=EDGE_LOOP('',(#1741));
#1743=FACE_BOUND('',#1742,.T.);
#1744=ORIENTED_EDGE('',*,*,#496,.T.);
#1745=EDGE_LOOP('',(#1744));
#1746=FACE_BOUND('',#1745,.T.);
#1747=ADVANCED_FACE('F1150',(#1743,#1746),#1732,.F.);
#1748=CARTESIAN_POINT('',(-49.4974746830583,49.4974746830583,10.));
#1749=DIRECTION('',(0.,0.,1.));
#1750=DIRECTION('',(1.,0.,0.));
#1751=AXIS2_PLACEMENT_3D('',#1748,#1749,#1750);
#1752=PLANE('',#1751);
#1753=ORIENTED_EDGE('',*,*,#1740,.T.);
#1754=EDGE_LOOP('',(#1753));
#1755=FACE_BOUND('',#1754,.T.);
#1756=ADVANCED_FACE('F1160',(#1755),#1752,.T.);
#1757=CARTESIAN_POINT('',(-49.4974746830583,-49.4974746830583,10.));
#1758=DIRECTION('',(0.,0.,1.));
#1759=DIRECTION('',(1.,0.,0.));
#1760=AXIS2_PLACEMENT_3D('',#1757,#1758,#1759);
#1761=CYLINDRICAL_SURFACE('',#1760,6.);
#1762=CARTESIAN_POINT('',(-49.4974746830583,-49.4974746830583,10.));
#1763=DIRECTION('',(0.,0.,1.));
#1764=DIRECTION('',(1.,0.,0.));
#1765=AXIS2_PLACEMENT_3D('',#1762,#1763,#1764);
#1766=CIRCLE('',#1765,6.);
#1767=CARTESIAN_POINT('',(-43.4974746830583,-49.4974746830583,10.));
#1768=VERTEX_POINT('',#1767);
#1769=EDGE_CURVE('E1312',#1768,#1768,#1766,.T.);
#1770=ORIENTED_EDGE('',*,*,#1769,.F.);
#1771=EDGE_LOOP('',(#1770));
#1772=FACE_BOUND('',#1771,.T.);
#1773=ORIENTED_EDGE('',*,*,#352,.T.);
#1774=EDGE_LOOP('',(#1773));
#1775=FACE_BOUND('',#1774,.T.);
#1776=ADVANCED_FACE('F1167',(#1772,#1775),#1761,.F.);
#1777=CARTESIAN_POINT('',(-49.4974746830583,-49.4974746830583,10.));
#1778=DIRECTION('',(0.,0.,1.));
#1779=DIRECTION('',(1.,0.,0.));
#1780=AXIS2_PLACEMENT_3D('',#1777,#1778,#1779);
#1781=PLANE('',#1780);
#1782=ORIENTED_EDGE('',*,*,#1769,.T.);
#1783=EDGE_LOOP('',(#1782));
#1784=FACE_BOUND('',#1783,.T.);
#1785=ADVANCED_FACE('F1180',(#1784),#1781,.T.);
#1786=CARTESIAN_POINT('',(-38.8029403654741,-16.0727041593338,0.));
#1787=DIRECTION('',(0.,0.,1.));
#1788=DIRECTION('',(1.,0.,0.));
#1789=AXIS2_PLACEMENT_3D('',#1786,#1787,#1788);
#1790=CYLINDRICAL_SURFACE('',#1789,2.5);
#1791=ORIENTED_EDGE('',*,*,#852,.F.);
#1792=EDGE_LOOP('',(#1791));
#1793=FACE_BOUND('',#1792,.T.);
#1794=ORIENTED_EDGE('',*,*,#968,.T.);
#1795=EDGE_LOOP('',(#1794));
#1796=FACE_BOUND('',#1795,.T.);
#1797=ADVANCED_FACE('F1183',(#1793,#1796),#1790,.F.);
#1798=CARTESIAN_POINT('',(38.802940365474,16.0727041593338,0.));
#1799=DIRECTION('',(0.,0.,1.));
#1800=DIRECTION('',(1.,0.,0.));
#1801=AXIS2_PLACEMENT_3D('',#1798,#1799,#1800);
#1802=CYLINDRICAL_SURFACE('',#1801,2.5);
#1803=ORIENTED_EDGE('',*,*,#841,.F.);
#1804=EDGE_LOOP('',(#1803));
#1805=FACE_BOUND('',#1804,.T.);
#1806=ORIENTED_EDGE('',*,*,#957,.T.);
#1807=EDGE_LOOP('',(#1806));
#1808=FACE_BOUND('',#1807,.T.);
#1809=ADVANCED_FACE('F1203',(#1805,#1808),#1802,.F.);
#1810=CARTESIAN_POINT('',(-38.802940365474,16.0727041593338,24.));
#1811=DIRECTION('',(0.,0.,1.));
#1812=DIRECTION('',(1.,0.,0.));
#1813=AXIS2_PLACEMENT_3D('',#1810,#1811,#1812);
#1814=CYLINDRICAL_SURFACE('',#1813,2.1);
#1815=CARTESIAN_POINT('',(-38.802940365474,16.0727041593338,24.));
#1816=DIRECTION('',(0.,0.,1.));
#1817=DIRECTION('',(1.,0.,0.));
#1818=AXIS2_PLACEMENT_3D('',#1815,#1816,#1817);
#1819=CIRCLE('',#1818,2.1);
#1820=CARTESIAN_POINT('',(-36.702940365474,16.0727041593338,24.));
#1821=VERTEX_POINT('',#1820);
#1822=EDGE_CURVE('E1278',#1821,#1821,#1819,.T.);
#1823=ORIENTED_EDGE('',*,*,#1822,.F.);
#1824=EDGE_LOOP('',(#1823));
#1825=FACE_BOUND('',#1824,.T.);
#1826=ORIENTED_EDGE('',*,*,#946,.T.);
#1827=EDGE_LOOP('',(#1826));
#1828=FACE_BOUND('',#1827,.T.);
#1829=ADVANCED_FACE('F1211',(#1825,#1828),#1814,.F.);
#1830=CARTESIAN_POINT('',(-38.802940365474,16.0727041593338,24.));
#1831=DIRECTION('',(0.,0.,1.));
#1832=DIRECTION('',(1.,0.,0.));
#1833=AXIS2_PLACEMENT_3D('',#1830,#1831,#1832);
#1834=PLANE('',#1833);
#1835=ORIENTED_EDGE('',*,*,#1822,.T.);
#1836=EDGE_LOOP('',(#1835));
#1837=FACE_BOUND('',#1836,.T.);
#1838=ADVANCED_FACE('F1227',(#1837),#1834,.T.);
#1839=CLOSED_SHELL('',(#46,#74,#102,#130,#158,#186,#214,#242,#270,#312,#339,#434,#461,#488,#540,
#592,#646,#698,#748,#788,#828,#933,#1129,#1141,#1153,#1165,#1177,#1189,#1201,#1213,#1225,#1245,
#1257,#1277,#1289,#1309,#1321,#1341,#1353,#1373,#1385,#1405,#1417,#1437,#1449,#1469,#1481,#1501,
#1513,#1525,#1537,#1549,#1561,#1592,#1616,#1640,#1657,#1669,#1689,#1698,#1718,#1727,#1747,#1756,
#1776,#1785,#1797,#1809,#1829,#1838));
#1840=MANIFOLD_SOLID_BREP('B2',#1839);
#1841=ADVANCED_BREP_SHAPE_REPRESENTATION('',(#18,#1840),#14);
#1842=SHAPE_DEFINITION_REPRESENTATION(#9,#1841);
ENDSEC;
END-ISO-10303-21;
